VERSION 5.7 ;
  NOWIREEXTENSIONATPIN ON ;
  DIVIDERCHAR "/" ;
  BUSBITCHARS "[]" ;
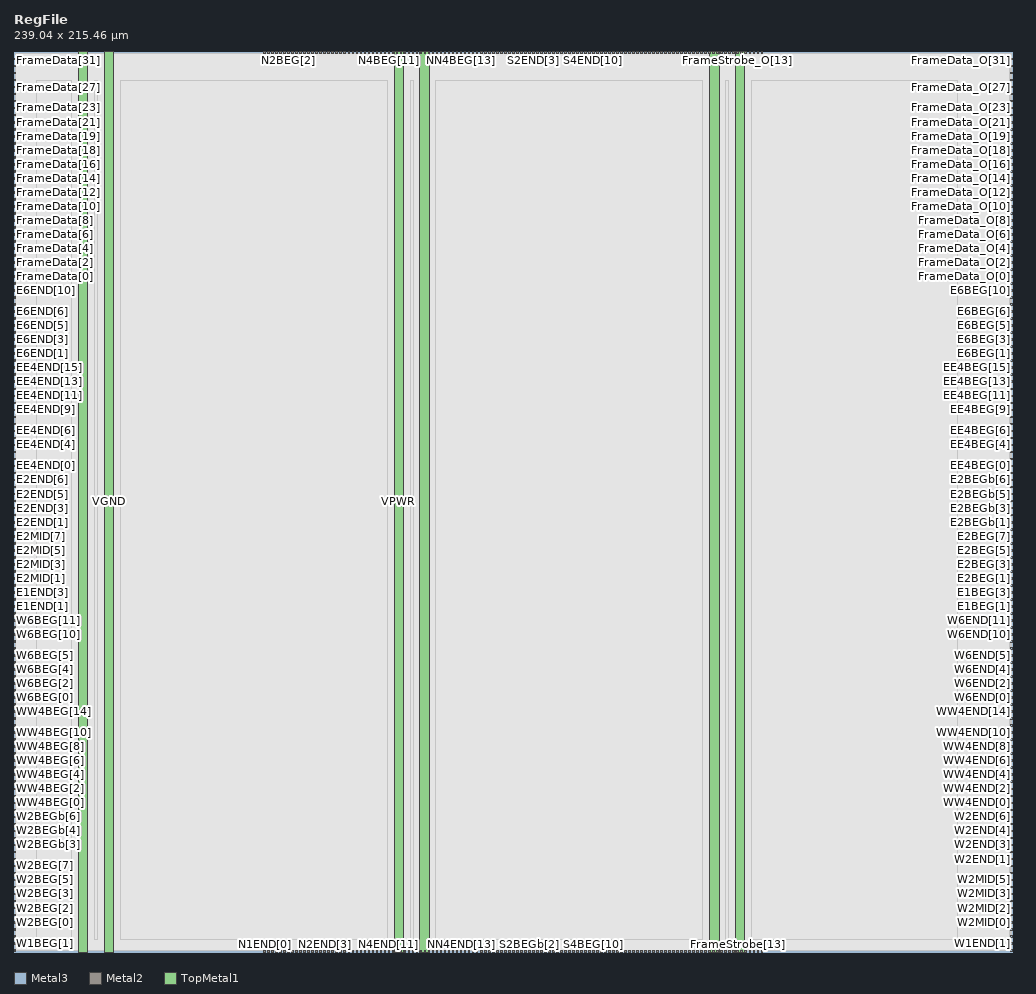
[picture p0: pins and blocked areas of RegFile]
MACRO RegFile
  CLASS BLOCK ;
  FOREIGN RegFile ;
  ORIGIN 0.000 0.000 ;
  SIZE 239.040 BY 215.460 ;
  PIN E1BEG[0]
    DIRECTION OUTPUT ;
    USE SIGNAL ;
    ANTENNADIFFAREA 0.708600 ;
    PORT
      LAYER Metal3 ;
        RECT 238.640 80.860 239.040 81.260 ;
    END
  END E1BEG[0]
  PIN E1BEG[1]
    DIRECTION OUTPUT ;
    USE SIGNAL ;
    ANTENNADIFFAREA 0.708600 ;
    PORT
      LAYER Metal3 ;
        RECT 238.640 82.540 239.040 82.940 ;
    END
  END E1BEG[1]
  PIN E1BEG[2]
    DIRECTION OUTPUT ;
    USE SIGNAL ;
    ANTENNADIFFAREA 0.708600 ;
    PORT
      LAYER Metal3 ;
        RECT 238.640 84.220 239.040 84.620 ;
    END
  END E1BEG[2]
  PIN E1BEG[3]
    DIRECTION OUTPUT ;
    USE SIGNAL ;
    ANTENNADIFFAREA 0.708600 ;
    PORT
      LAYER Metal3 ;
        RECT 238.640 85.900 239.040 86.300 ;
    END
  END E1BEG[3]
  PIN E1END[0]
    DIRECTION INPUT ;
    USE SIGNAL ;
    ANTENNAGATEAREA 1.931800 ;
    PORT
      LAYER Metal3 ;
        RECT 0.000 80.860 0.400 81.260 ;
    END
  END E1END[0]
  PIN E1END[1]
    DIRECTION INPUT ;
    USE SIGNAL ;
    ANTENNAGATEAREA 1.918800 ;
    PORT
      LAYER Metal3 ;
        RECT 0.000 82.540 0.400 82.940 ;
    END
  END E1END[1]
  PIN E1END[2]
    DIRECTION INPUT ;
    USE SIGNAL ;
    ANTENNAGATEAREA 2.371200 ;
    PORT
      LAYER Metal3 ;
        RECT 0.000 84.220 0.400 84.620 ;
    END
  END E1END[2]
  PIN E1END[3]
    DIRECTION INPUT ;
    USE SIGNAL ;
    ANTENNAGATEAREA 2.402400 ;
    PORT
      LAYER Metal3 ;
        RECT 0.000 85.900 0.400 86.300 ;
    END
  END E1END[3]
  PIN E2BEG[0]
    DIRECTION OUTPUT ;
    USE SIGNAL ;
    ANTENNADIFFAREA 0.708600 ;
    PORT
      LAYER Metal3 ;
        RECT 238.640 87.580 239.040 87.980 ;
    END
  END E2BEG[0]
  PIN E2BEG[1]
    DIRECTION OUTPUT ;
    USE SIGNAL ;
    ANTENNADIFFAREA 0.708600 ;
    PORT
      LAYER Metal3 ;
        RECT 238.640 89.260 239.040 89.660 ;
    END
  END E2BEG[1]
  PIN E2BEG[2]
    DIRECTION OUTPUT ;
    USE SIGNAL ;
    ANTENNADIFFAREA 0.708600 ;
    PORT
      LAYER Metal3 ;
        RECT 238.640 90.940 239.040 91.340 ;
    END
  END E2BEG[2]
  PIN E2BEG[3]
    DIRECTION OUTPUT ;
    USE SIGNAL ;
    ANTENNADIFFAREA 0.708600 ;
    PORT
      LAYER Metal3 ;
        RECT 238.640 92.620 239.040 93.020 ;
    END
  END E2BEG[3]
  PIN E2BEG[4]
    DIRECTION OUTPUT ;
    USE SIGNAL ;
    ANTENNADIFFAREA 0.708600 ;
    PORT
      LAYER Metal3 ;
        RECT 238.640 94.300 239.040 94.700 ;
    END
  END E2BEG[4]
  PIN E2BEG[5]
    DIRECTION OUTPUT ;
    USE SIGNAL ;
    ANTENNADIFFAREA 0.708600 ;
    PORT
      LAYER Metal3 ;
        RECT 238.640 95.980 239.040 96.380 ;
    END
  END E2BEG[5]
  PIN E2BEG[6]
    DIRECTION OUTPUT ;
    USE SIGNAL ;
    ANTENNADIFFAREA 0.708600 ;
    PORT
      LAYER Metal3 ;
        RECT 238.640 97.660 239.040 98.060 ;
    END
  END E2BEG[6]
  PIN E2BEG[7]
    DIRECTION OUTPUT ;
    USE SIGNAL ;
    ANTENNADIFFAREA 0.708600 ;
    PORT
      LAYER Metal3 ;
        RECT 238.640 99.340 239.040 99.740 ;
    END
  END E2BEG[7]
  PIN E2BEGb[0]
    DIRECTION OUTPUT ;
    USE SIGNAL ;
    ANTENNADIFFAREA 0.708600 ;
    PORT
      LAYER Metal3 ;
        RECT 238.640 101.020 239.040 101.420 ;
    END
  END E2BEGb[0]
  PIN E2BEGb[1]
    DIRECTION OUTPUT ;
    USE SIGNAL ;
    ANTENNADIFFAREA 0.708600 ;
    PORT
      LAYER Metal3 ;
        RECT 238.640 102.700 239.040 103.100 ;
    END
  END E2BEGb[1]
  PIN E2BEGb[2]
    DIRECTION OUTPUT ;
    USE SIGNAL ;
    ANTENNADIFFAREA 0.708600 ;
    PORT
      LAYER Metal3 ;
        RECT 238.640 104.380 239.040 104.780 ;
    END
  END E2BEGb[2]
  PIN E2BEGb[3]
    DIRECTION OUTPUT ;
    USE SIGNAL ;
    ANTENNADIFFAREA 0.708600 ;
    PORT
      LAYER Metal3 ;
        RECT 238.640 106.060 239.040 106.460 ;
    END
  END E2BEGb[3]
  PIN E2BEGb[4]
    DIRECTION OUTPUT ;
    USE SIGNAL ;
    ANTENNADIFFAREA 0.708600 ;
    PORT
      LAYER Metal3 ;
        RECT 238.640 107.740 239.040 108.140 ;
    END
  END E2BEGb[4]
  PIN E2BEGb[5]
    DIRECTION OUTPUT ;
    USE SIGNAL ;
    ANTENNADIFFAREA 0.708600 ;
    PORT
      LAYER Metal3 ;
        RECT 238.640 109.420 239.040 109.820 ;
    END
  END E2BEGb[5]
  PIN E2BEGb[6]
    DIRECTION OUTPUT ;
    USE SIGNAL ;
    ANTENNADIFFAREA 0.708600 ;
    PORT
      LAYER Metal3 ;
        RECT 238.640 111.100 239.040 111.500 ;
    END
  END E2BEGb[6]
  PIN E2BEGb[7]
    DIRECTION OUTPUT ;
    USE SIGNAL ;
    ANTENNADIFFAREA 0.708600 ;
    PORT
      LAYER Metal3 ;
        RECT 238.640 112.780 239.040 113.180 ;
    END
  END E2BEGb[7]
  PIN E2END[0]
    DIRECTION INPUT ;
    USE SIGNAL ;
    ANTENNAGATEAREA 1.079000 ;
    PORT
      LAYER Metal3 ;
        RECT 0.000 101.020 0.400 101.420 ;
    END
  END E2END[0]
  PIN E2END[1]
    DIRECTION INPUT ;
    USE SIGNAL ;
    ANTENNAGATEAREA 1.033500 ;
    PORT
      LAYER Metal3 ;
        RECT 0.000 102.700 0.400 103.100 ;
    END
  END E2END[1]
  PIN E2END[2]
    DIRECTION INPUT ;
    USE SIGNAL ;
    ANTENNAGATEAREA 1.701700 ;
    PORT
      LAYER Metal3 ;
        RECT 0.000 104.380 0.400 104.780 ;
    END
  END E2END[2]
  PIN E2END[3]
    DIRECTION INPUT ;
    USE SIGNAL ;
    ANTENNAGATEAREA 1.701700 ;
    PORT
      LAYER Metal3 ;
        RECT 0.000 106.060 0.400 106.460 ;
    END
  END E2END[3]
  PIN E2END[4]
    DIRECTION INPUT ;
    USE SIGNAL ;
    ANTENNAGATEAREA 1.079000 ;
    PORT
      LAYER Metal3 ;
        RECT 0.000 107.740 0.400 108.140 ;
    END
  END E2END[4]
  PIN E2END[5]
    DIRECTION INPUT ;
    USE SIGNAL ;
    ANTENNAGATEAREA 1.279200 ;
    PORT
      LAYER Metal3 ;
        RECT 0.000 109.420 0.400 109.820 ;
    END
  END E2END[5]
  PIN E2END[6]
    DIRECTION INPUT ;
    USE SIGNAL ;
    ANTENNAGATEAREA 1.292200 ;
    PORT
      LAYER Metal3 ;
        RECT 0.000 111.100 0.400 111.500 ;
    END
  END E2END[6]
  PIN E2END[7]
    DIRECTION INPUT ;
    USE SIGNAL ;
    ANTENNAGATEAREA 1.033500 ;
    PORT
      LAYER Metal3 ;
        RECT 0.000 112.780 0.400 113.180 ;
    END
  END E2END[7]
  PIN E2MID[0]
    DIRECTION INPUT ;
    USE SIGNAL ;
    ANTENNAGATEAREA 0.816400 ;
    PORT
      LAYER Metal3 ;
        RECT 0.000 87.580 0.400 87.980 ;
    END
  END E2MID[0]
  PIN E2MID[1]
    DIRECTION INPUT ;
    USE SIGNAL ;
    ANTENNAGATEAREA 1.014000 ;
    PORT
      LAYER Metal3 ;
        RECT 0.000 89.260 0.400 89.660 ;
    END
  END E2MID[1]
  PIN E2MID[2]
    DIRECTION INPUT ;
    USE SIGNAL ;
    ANTENNAGATEAREA 0.820300 ;
    PORT
      LAYER Metal3 ;
        RECT 0.000 90.940 0.400 91.340 ;
    END
  END E2MID[2]
  PIN E2MID[3]
    DIRECTION INPUT ;
    USE SIGNAL ;
    ANTENNAGATEAREA 1.033500 ;
    PORT
      LAYER Metal3 ;
        RECT 0.000 92.620 0.400 93.020 ;
    END
  END E2MID[3]
  PIN E2MID[4]
    DIRECTION INPUT ;
    USE SIGNAL ;
    ANTENNAGATEAREA 0.820300 ;
    PORT
      LAYER Metal3 ;
        RECT 0.000 94.300 0.400 94.700 ;
    END
  END E2MID[4]
  PIN E2MID[5]
    DIRECTION INPUT ;
    USE SIGNAL ;
    ANTENNAGATEAREA 1.033500 ;
    PORT
      LAYER Metal3 ;
        RECT 0.000 95.980 0.400 96.380 ;
    END
  END E2MID[5]
  PIN E2MID[6]
    DIRECTION INPUT ;
    USE SIGNAL ;
    ANTENNAGATEAREA 0.787800 ;
    PORT
      LAYER Metal3 ;
        RECT 0.000 97.660 0.400 98.060 ;
    END
  END E2MID[6]
  PIN E2MID[7]
    DIRECTION INPUT ;
    USE SIGNAL ;
    ANTENNAGATEAREA 1.001000 ;
    PORT
      LAYER Metal3 ;
        RECT 0.000 99.340 0.400 99.740 ;
    END
  END E2MID[7]
  PIN E6BEG[0]
    DIRECTION OUTPUT ;
    USE SIGNAL ;
    ANTENNADIFFAREA 0.708600 ;
    PORT
      LAYER Metal3 ;
        RECT 238.640 141.340 239.040 141.740 ;
    END
  END E6BEG[0]
  PIN E6BEG[10]
    DIRECTION OUTPUT ;
    USE SIGNAL ;
    ANTENNADIFFAREA 0.708600 ;
    PORT
      LAYER Metal3 ;
        RECT 238.640 158.140 239.040 158.540 ;
    END
  END E6BEG[10]
  PIN E6BEG[11]
    DIRECTION OUTPUT ;
    USE SIGNAL ;
    ANTENNADIFFAREA 0.708600 ;
    PORT
      LAYER Metal3 ;
        RECT 238.640 159.820 239.040 160.220 ;
    END
  END E6BEG[11]
  PIN E6BEG[1]
    DIRECTION OUTPUT ;
    USE SIGNAL ;
    ANTENNADIFFAREA 0.708600 ;
    PORT
      LAYER Metal3 ;
        RECT 238.640 143.020 239.040 143.420 ;
    END
  END E6BEG[1]
  PIN E6BEG[2]
    DIRECTION OUTPUT ;
    USE SIGNAL ;
    ANTENNADIFFAREA 0.708600 ;
    PORT
      LAYER Metal3 ;
        RECT 238.640 144.700 239.040 145.100 ;
    END
  END E6BEG[2]
  PIN E6BEG[3]
    DIRECTION OUTPUT ;
    USE SIGNAL ;
    ANTENNADIFFAREA 0.708600 ;
    PORT
      LAYER Metal3 ;
        RECT 238.640 146.380 239.040 146.780 ;
    END
  END E6BEG[3]
  PIN E6BEG[4]
    DIRECTION OUTPUT ;
    USE SIGNAL ;
    ANTENNADIFFAREA 0.708600 ;
    PORT
      LAYER Metal3 ;
        RECT 238.640 148.060 239.040 148.460 ;
    END
  END E6BEG[4]
  PIN E6BEG[5]
    DIRECTION OUTPUT ;
    USE SIGNAL ;
    ANTENNADIFFAREA 0.708600 ;
    PORT
      LAYER Metal3 ;
        RECT 238.640 149.740 239.040 150.140 ;
    END
  END E6BEG[5]
  PIN E6BEG[6]
    DIRECTION OUTPUT ;
    USE SIGNAL ;
    ANTENNADIFFAREA 0.708600 ;
    PORT
      LAYER Metal3 ;
        RECT 238.640 151.420 239.040 151.820 ;
    END
  END E6BEG[6]
  PIN E6BEG[7]
    DIRECTION OUTPUT ;
    USE SIGNAL ;
    ANTENNADIFFAREA 0.708600 ;
    PORT
      LAYER Metal3 ;
        RECT 238.640 153.100 239.040 153.500 ;
    END
  END E6BEG[7]
  PIN E6BEG[8]
    DIRECTION OUTPUT ;
    USE SIGNAL ;
    ANTENNADIFFAREA 0.708600 ;
    PORT
      LAYER Metal3 ;
        RECT 238.640 154.780 239.040 155.180 ;
    END
  END E6BEG[8]
  PIN E6BEG[9]
    DIRECTION OUTPUT ;
    USE SIGNAL ;
    ANTENNADIFFAREA 0.708600 ;
    PORT
      LAYER Metal3 ;
        RECT 238.640 156.460 239.040 156.860 ;
    END
  END E6BEG[9]
  PIN E6END[0]
    DIRECTION INPUT ;
    USE SIGNAL ;
    ANTENNAGATEAREA 2.596100 ;
    PORT
      LAYER Metal3 ;
        RECT 0.000 141.340 0.400 141.740 ;
    END
  END E6END[0]
  PIN E6END[10]
    DIRECTION INPUT ;
    USE SIGNAL ;
    ANTENNAGATEAREA 0.180700 ;
    PORT
      LAYER Metal3 ;
        RECT 0.000 158.140 0.400 158.540 ;
    END
  END E6END[10]
  PIN E6END[11]
    DIRECTION INPUT ;
    USE SIGNAL ;
    ANTENNAGATEAREA 0.180700 ;
    PORT
      LAYER Metal3 ;
        RECT 0.000 159.820 0.400 160.220 ;
    END
  END E6END[11]
  PIN E6END[1]
    DIRECTION INPUT ;
    USE SIGNAL ;
    ANTENNAGATEAREA 2.567500 ;
    PORT
      LAYER Metal3 ;
        RECT 0.000 143.020 0.400 143.420 ;
    END
  END E6END[1]
  PIN E6END[2]
    DIRECTION INPUT ;
    USE SIGNAL ;
    ANTENNAGATEAREA 0.180700 ;
    PORT
      LAYER Metal3 ;
        RECT 0.000 144.700 0.400 145.100 ;
    END
  END E6END[2]
  PIN E6END[3]
    DIRECTION INPUT ;
    USE SIGNAL ;
    ANTENNAGATEAREA 0.180700 ;
    PORT
      LAYER Metal3 ;
        RECT 0.000 146.380 0.400 146.780 ;
    END
  END E6END[3]
  PIN E6END[4]
    DIRECTION INPUT ;
    USE SIGNAL ;
    ANTENNAGATEAREA 0.180700 ;
    PORT
      LAYER Metal3 ;
        RECT 0.000 148.060 0.400 148.460 ;
    END
  END E6END[4]
  PIN E6END[5]
    DIRECTION INPUT ;
    USE SIGNAL ;
    ANTENNAGATEAREA 0.180700 ;
    PORT
      LAYER Metal3 ;
        RECT 0.000 149.740 0.400 150.140 ;
    END
  END E6END[5]
  PIN E6END[6]
    DIRECTION INPUT ;
    USE SIGNAL ;
    ANTENNAGATEAREA 0.180700 ;
    PORT
      LAYER Metal3 ;
        RECT 0.000 151.420 0.400 151.820 ;
    END
  END E6END[6]
  PIN E6END[7]
    DIRECTION INPUT ;
    USE SIGNAL ;
    ANTENNAGATEAREA 0.180700 ;
    PORT
      LAYER Metal3 ;
        RECT 0.000 153.100 0.400 153.500 ;
    END
  END E6END[7]
  PIN E6END[8]
    DIRECTION INPUT ;
    USE SIGNAL ;
    ANTENNAGATEAREA 0.180700 ;
    PORT
      LAYER Metal3 ;
        RECT 0.000 154.780 0.400 155.180 ;
    END
  END E6END[8]
  PIN E6END[9]
    DIRECTION INPUT ;
    USE SIGNAL ;
    ANTENNAGATEAREA 0.180700 ;
    PORT
      LAYER Metal3 ;
        RECT 0.000 156.460 0.400 156.860 ;
    END
  END E6END[9]
  PIN EE4BEG[0]
    DIRECTION OUTPUT ;
    USE SIGNAL ;
    ANTENNADIFFAREA 0.708600 ;
    PORT
      LAYER Metal3 ;
        RECT 238.640 114.460 239.040 114.860 ;
    END
  END EE4BEG[0]
  PIN EE4BEG[10]
    DIRECTION OUTPUT ;
    USE SIGNAL ;
    ANTENNADIFFAREA 0.708600 ;
    PORT
      LAYER Metal3 ;
        RECT 238.640 131.260 239.040 131.660 ;
    END
  END EE4BEG[10]
  PIN EE4BEG[11]
    DIRECTION OUTPUT ;
    USE SIGNAL ;
    ANTENNADIFFAREA 0.708600 ;
    PORT
      LAYER Metal3 ;
        RECT 238.640 132.940 239.040 133.340 ;
    END
  END EE4BEG[11]
  PIN EE4BEG[12]
    DIRECTION OUTPUT ;
    USE SIGNAL ;
    ANTENNADIFFAREA 0.708600 ;
    PORT
      LAYER Metal3 ;
        RECT 238.640 134.620 239.040 135.020 ;
    END
  END EE4BEG[12]
  PIN EE4BEG[13]
    DIRECTION OUTPUT ;
    USE SIGNAL ;
    ANTENNADIFFAREA 0.708600 ;
    PORT
      LAYER Metal3 ;
        RECT 238.640 136.300 239.040 136.700 ;
    END
  END EE4BEG[13]
  PIN EE4BEG[14]
    DIRECTION OUTPUT ;
    USE SIGNAL ;
    ANTENNADIFFAREA 0.708600 ;
    PORT
      LAYER Metal3 ;
        RECT 238.640 137.980 239.040 138.380 ;
    END
  END EE4BEG[14]
  PIN EE4BEG[15]
    DIRECTION OUTPUT ;
    USE SIGNAL ;
    ANTENNADIFFAREA 0.708600 ;
    PORT
      LAYER Metal3 ;
        RECT 238.640 139.660 239.040 140.060 ;
    END
  END EE4BEG[15]
  PIN EE4BEG[1]
    DIRECTION OUTPUT ;
    USE SIGNAL ;
    ANTENNADIFFAREA 0.708600 ;
    PORT
      LAYER Metal3 ;
        RECT 238.640 116.140 239.040 116.540 ;
    END
  END EE4BEG[1]
  PIN EE4BEG[2]
    DIRECTION OUTPUT ;
    USE SIGNAL ;
    ANTENNADIFFAREA 0.708600 ;
    PORT
      LAYER Metal3 ;
        RECT 238.640 117.820 239.040 118.220 ;
    END
  END EE4BEG[2]
  PIN EE4BEG[3]
    DIRECTION OUTPUT ;
    USE SIGNAL ;
    ANTENNADIFFAREA 0.708600 ;
    PORT
      LAYER Metal3 ;
        RECT 238.640 119.500 239.040 119.900 ;
    END
  END EE4BEG[3]
  PIN EE4BEG[4]
    DIRECTION OUTPUT ;
    USE SIGNAL ;
    ANTENNADIFFAREA 0.708600 ;
    PORT
      LAYER Metal3 ;
        RECT 238.640 121.180 239.040 121.580 ;
    END
  END EE4BEG[4]
  PIN EE4BEG[5]
    DIRECTION OUTPUT ;
    USE SIGNAL ;
    ANTENNADIFFAREA 0.708600 ;
    PORT
      LAYER Metal3 ;
        RECT 238.640 122.860 239.040 123.260 ;
    END
  END EE4BEG[5]
  PIN EE4BEG[6]
    DIRECTION OUTPUT ;
    USE SIGNAL ;
    ANTENNADIFFAREA 0.708600 ;
    PORT
      LAYER Metal3 ;
        RECT 238.640 124.540 239.040 124.940 ;
    END
  END EE4BEG[6]
  PIN EE4BEG[7]
    DIRECTION OUTPUT ;
    USE SIGNAL ;
    ANTENNADIFFAREA 0.708600 ;
    PORT
      LAYER Metal3 ;
        RECT 238.640 126.220 239.040 126.620 ;
    END
  END EE4BEG[7]
  PIN EE4BEG[8]
    DIRECTION OUTPUT ;
    USE SIGNAL ;
    ANTENNADIFFAREA 0.708600 ;
    PORT
      LAYER Metal3 ;
        RECT 238.640 127.900 239.040 128.300 ;
    END
  END EE4BEG[8]
  PIN EE4BEG[9]
    DIRECTION OUTPUT ;
    USE SIGNAL ;
    ANTENNADIFFAREA 0.708600 ;
    PORT
      LAYER Metal3 ;
        RECT 238.640 129.580 239.040 129.980 ;
    END
  END EE4BEG[9]
  PIN EE4END[0]
    DIRECTION INPUT ;
    USE SIGNAL ;
    ANTENNAGATEAREA 0.881400 ;
    PORT
      LAYER Metal3 ;
        RECT 0.000 114.460 0.400 114.860 ;
    END
  END EE4END[0]
  PIN EE4END[10]
    DIRECTION INPUT ;
    USE SIGNAL ;
    ANTENNAGATEAREA 0.789100 ;
    ANTENNADIFFAREA 2.015400 ;
    PORT
      LAYER Metal3 ;
        RECT 0.000 131.260 0.400 131.660 ;
    END
  END EE4END[10]
  PIN EE4END[11]
    DIRECTION INPUT ;
    USE SIGNAL ;
    ANTENNAGATEAREA 0.789100 ;
    ANTENNADIFFAREA 2.015400 ;
    PORT
      LAYER Metal3 ;
        RECT 0.000 132.940 0.400 133.340 ;
    END
  END EE4END[11]
  PIN EE4END[12]
    DIRECTION INPUT ;
    USE SIGNAL ;
    ANTENNAGATEAREA 0.789100 ;
    ANTENNADIFFAREA 2.015400 ;
    PORT
      LAYER Metal3 ;
        RECT 0.000 134.620 0.400 135.020 ;
    END
  END EE4END[12]
  PIN EE4END[13]
    DIRECTION INPUT ;
    USE SIGNAL ;
    ANTENNAGATEAREA 0.180700 ;
    PORT
      LAYER Metal3 ;
        RECT 0.000 136.300 0.400 136.700 ;
    END
  END EE4END[13]
  PIN EE4END[14]
    DIRECTION INPUT ;
    USE SIGNAL ;
    ANTENNAGATEAREA 0.180700 ;
    PORT
      LAYER Metal3 ;
        RECT 0.000 137.980 0.400 138.380 ;
    END
  END EE4END[14]
  PIN EE4END[15]
    DIRECTION INPUT ;
    USE SIGNAL ;
    ANTENNAGATEAREA 0.789100 ;
    ANTENNADIFFAREA 2.015400 ;
    PORT
      LAYER Metal3 ;
        RECT 0.000 139.660 0.400 140.060 ;
    END
  END EE4END[15]
  PIN EE4END[1]
    DIRECTION INPUT ;
    USE SIGNAL ;
    ANTENNAGATEAREA 0.852800 ;
    PORT
      LAYER Metal3 ;
        RECT 0.000 116.140 0.400 116.540 ;
    END
  END EE4END[1]
  PIN EE4END[2]
    DIRECTION INPUT ;
    USE SIGNAL ;
    ANTENNAGATEAREA 0.852800 ;
    PORT
      LAYER Metal3 ;
        RECT 0.000 117.820 0.400 118.220 ;
    END
  END EE4END[2]
  PIN EE4END[3]
    DIRECTION INPUT ;
    USE SIGNAL ;
    ANTENNAGATEAREA 0.878800 ;
    PORT
      LAYER Metal3 ;
        RECT 0.000 119.500 0.400 119.900 ;
    END
  END EE4END[3]
  PIN EE4END[4]
    DIRECTION INPUT ;
    USE SIGNAL ;
    ANTENNAGATEAREA 0.789100 ;
    ANTENNADIFFAREA 2.015400 ;
    PORT
      LAYER Metal3 ;
        RECT 0.000 121.180 0.400 121.580 ;
    END
  END EE4END[4]
  PIN EE4END[5]
    DIRECTION INPUT ;
    USE SIGNAL ;
    ANTENNAGATEAREA 0.789100 ;
    ANTENNADIFFAREA 2.015400 ;
    PORT
      LAYER Metal3 ;
        RECT 0.000 122.860 0.400 123.260 ;
    END
  END EE4END[5]
  PIN EE4END[6]
    DIRECTION INPUT ;
    USE SIGNAL ;
    ANTENNAGATEAREA 0.789100 ;
    ANTENNADIFFAREA 2.015400 ;
    PORT
      LAYER Metal3 ;
        RECT 0.000 124.540 0.400 124.940 ;
    END
  END EE4END[6]
  PIN EE4END[7]
    DIRECTION INPUT ;
    USE SIGNAL ;
    ANTENNAGATEAREA 0.789100 ;
    ANTENNADIFFAREA 2.015400 ;
    PORT
      LAYER Metal3 ;
        RECT 0.000 126.220 0.400 126.620 ;
    END
  END EE4END[7]
  PIN EE4END[8]
    DIRECTION INPUT ;
    USE SIGNAL ;
    ANTENNAGATEAREA 0.789100 ;
    ANTENNADIFFAREA 2.015400 ;
    PORT
      LAYER Metal3 ;
        RECT 0.000 127.900 0.400 128.300 ;
    END
  END EE4END[8]
  PIN EE4END[9]
    DIRECTION INPUT ;
    USE SIGNAL ;
    ANTENNAGATEAREA 0.789100 ;
    ANTENNADIFFAREA 2.015400 ;
    PORT
      LAYER Metal3 ;
        RECT 0.000 129.580 0.400 129.980 ;
    END
  END EE4END[9]
  PIN FrameData[0]
    DIRECTION INPUT ;
    USE SIGNAL ;
    ANTENNAGATEAREA 2.349100 ;
    PORT
      LAYER Metal3 ;
        RECT 0.000 161.500 0.400 161.900 ;
    END
  END FrameData[0]
  PIN FrameData[10]
    DIRECTION INPUT ;
    USE SIGNAL ;
    ANTENNAGATEAREA 2.529800 ;
    PORT
      LAYER Metal3 ;
        RECT 0.000 178.300 0.400 178.700 ;
    END
  END FrameData[10]
  PIN FrameData[11]
    DIRECTION INPUT ;
    USE SIGNAL ;
    ANTENNAGATEAREA 2.529800 ;
    PORT
      LAYER Metal3 ;
        RECT 0.000 179.980 0.400 180.380 ;
    END
  END FrameData[11]
  PIN FrameData[12]
    DIRECTION INPUT ;
    USE SIGNAL ;
    ANTENNAGATEAREA 2.529800 ;
    PORT
      LAYER Metal3 ;
        RECT 0.000 181.660 0.400 182.060 ;
    END
  END FrameData[12]
  PIN FrameData[13]
    DIRECTION INPUT ;
    USE SIGNAL ;
    ANTENNAGATEAREA 2.529800 ;
    PORT
      LAYER Metal3 ;
        RECT 0.000 183.340 0.400 183.740 ;
    END
  END FrameData[13]
  PIN FrameData[14]
    DIRECTION INPUT ;
    USE SIGNAL ;
    ANTENNAGATEAREA 2.529800 ;
    PORT
      LAYER Metal3 ;
        RECT 0.000 185.020 0.400 185.420 ;
    END
  END FrameData[14]
  PIN FrameData[15]
    DIRECTION INPUT ;
    USE SIGNAL ;
    ANTENNAGATEAREA 2.529800 ;
    PORT
      LAYER Metal3 ;
        RECT 0.000 186.700 0.400 187.100 ;
    END
  END FrameData[15]
  PIN FrameData[16]
    DIRECTION INPUT ;
    USE SIGNAL ;
    ANTENNAGATEAREA 2.529800 ;
    PORT
      LAYER Metal3 ;
        RECT 0.000 188.380 0.400 188.780 ;
    END
  END FrameData[16]
  PIN FrameData[17]
    DIRECTION INPUT ;
    USE SIGNAL ;
    ANTENNAGATEAREA 2.529800 ;
    PORT
      LAYER Metal3 ;
        RECT 0.000 190.060 0.400 190.460 ;
    END
  END FrameData[17]
  PIN FrameData[18]
    DIRECTION INPUT ;
    USE SIGNAL ;
    ANTENNAGATEAREA 2.529800 ;
    PORT
      LAYER Metal3 ;
        RECT 0.000 191.740 0.400 192.140 ;
    END
  END FrameData[18]
  PIN FrameData[19]
    DIRECTION INPUT ;
    USE SIGNAL ;
    ANTENNAGATEAREA 2.529800 ;
    PORT
      LAYER Metal3 ;
        RECT 0.000 193.420 0.400 193.820 ;
    END
  END FrameData[19]
  PIN FrameData[1]
    DIRECTION INPUT ;
    USE SIGNAL ;
    ANTENNAGATEAREA 2.349100 ;
    PORT
      LAYER Metal3 ;
        RECT 0.000 163.180 0.400 163.580 ;
    END
  END FrameData[1]
  PIN FrameData[20]
    DIRECTION INPUT ;
    USE SIGNAL ;
    ANTENNAGATEAREA 2.529800 ;
    PORT
      LAYER Metal3 ;
        RECT 0.000 195.100 0.400 195.500 ;
    END
  END FrameData[20]
  PIN FrameData[21]
    DIRECTION INPUT ;
    USE SIGNAL ;
    ANTENNAGATEAREA 2.529800 ;
    PORT
      LAYER Metal3 ;
        RECT 0.000 196.780 0.400 197.180 ;
    END
  END FrameData[21]
  PIN FrameData[22]
    DIRECTION INPUT ;
    USE SIGNAL ;
    ANTENNAGATEAREA 2.529800 ;
    PORT
      LAYER Metal3 ;
        RECT 0.000 198.460 0.400 198.860 ;
    END
  END FrameData[22]
  PIN FrameData[23]
    DIRECTION INPUT ;
    USE SIGNAL ;
    ANTENNAGATEAREA 2.529800 ;
    PORT
      LAYER Metal3 ;
        RECT 0.000 200.140 0.400 200.540 ;
    END
  END FrameData[23]
  PIN FrameData[24]
    DIRECTION INPUT ;
    USE SIGNAL ;
    ANTENNAGATEAREA 2.529800 ;
    PORT
      LAYER Metal3 ;
        RECT 0.000 201.820 0.400 202.220 ;
    END
  END FrameData[24]
  PIN FrameData[25]
    DIRECTION INPUT ;
    USE SIGNAL ;
    ANTENNAGATEAREA 2.529800 ;
    PORT
      LAYER Metal3 ;
        RECT 0.000 203.500 0.400 203.900 ;
    END
  END FrameData[25]
  PIN FrameData[26]
    DIRECTION INPUT ;
    USE SIGNAL ;
    ANTENNAGATEAREA 2.529800 ;
    PORT
      LAYER Metal3 ;
        RECT 0.000 205.180 0.400 205.580 ;
    END
  END FrameData[26]
  PIN FrameData[27]
    DIRECTION INPUT ;
    USE SIGNAL ;
    ANTENNAGATEAREA 2.529800 ;
    PORT
      LAYER Metal3 ;
        RECT 0.000 206.860 0.400 207.260 ;
    END
  END FrameData[27]
  PIN FrameData[28]
    DIRECTION INPUT ;
    USE SIGNAL ;
    ANTENNAGATEAREA 2.529800 ;
    PORT
      LAYER Metal3 ;
        RECT 0.000 208.540 0.400 208.940 ;
    END
  END FrameData[28]
  PIN FrameData[29]
    DIRECTION INPUT ;
    USE SIGNAL ;
    ANTENNAGATEAREA 2.529800 ;
    PORT
      LAYER Metal3 ;
        RECT 0.000 210.220 0.400 210.620 ;
    END
  END FrameData[29]
  PIN FrameData[2]
    DIRECTION INPUT ;
    USE SIGNAL ;
    ANTENNAGATEAREA 2.529800 ;
    PORT
      LAYER Metal3 ;
        RECT 0.000 164.860 0.400 165.260 ;
    END
  END FrameData[2]
  PIN FrameData[30]
    DIRECTION INPUT ;
    USE SIGNAL ;
    ANTENNAGATEAREA 2.529800 ;
    PORT
      LAYER Metal3 ;
        RECT 0.000 211.900 0.400 212.300 ;
    END
  END FrameData[30]
  PIN FrameData[31]
    DIRECTION INPUT ;
    USE SIGNAL ;
    ANTENNAGATEAREA 2.529800 ;
    PORT
      LAYER Metal3 ;
        RECT 0.000 213.580 0.400 213.980 ;
    END
  END FrameData[31]
  PIN FrameData[3]
    DIRECTION INPUT ;
    USE SIGNAL ;
    ANTENNAGATEAREA 2.529800 ;
    PORT
      LAYER Metal3 ;
        RECT 0.000 166.540 0.400 166.940 ;
    END
  END FrameData[3]
  PIN FrameData[4]
    DIRECTION INPUT ;
    USE SIGNAL ;
    ANTENNAGATEAREA 2.529800 ;
    PORT
      LAYER Metal3 ;
        RECT 0.000 168.220 0.400 168.620 ;
    END
  END FrameData[4]
  PIN FrameData[5]
    DIRECTION INPUT ;
    USE SIGNAL ;
    ANTENNAGATEAREA 2.529800 ;
    PORT
      LAYER Metal3 ;
        RECT 0.000 169.900 0.400 170.300 ;
    END
  END FrameData[5]
  PIN FrameData[6]
    DIRECTION INPUT ;
    USE SIGNAL ;
    ANTENNAGATEAREA 2.529800 ;
    PORT
      LAYER Metal3 ;
        RECT 0.000 171.580 0.400 171.980 ;
    END
  END FrameData[6]
  PIN FrameData[7]
    DIRECTION INPUT ;
    USE SIGNAL ;
    ANTENNAGATEAREA 2.529800 ;
    PORT
      LAYER Metal3 ;
        RECT 0.000 173.260 0.400 173.660 ;
    END
  END FrameData[7]
  PIN FrameData[8]
    DIRECTION INPUT ;
    USE SIGNAL ;
    ANTENNAGATEAREA 2.529800 ;
    PORT
      LAYER Metal3 ;
        RECT 0.000 174.940 0.400 175.340 ;
    END
  END FrameData[8]
  PIN FrameData[9]
    DIRECTION INPUT ;
    USE SIGNAL ;
    ANTENNAGATEAREA 2.529800 ;
    PORT
      LAYER Metal3 ;
        RECT 0.000 176.620 0.400 177.020 ;
    END
  END FrameData[9]
  PIN FrameData_O[0]
    DIRECTION OUTPUT ;
    USE SIGNAL ;
    ANTENNADIFFAREA 0.708600 ;
    PORT
      LAYER Metal3 ;
        RECT 238.640 161.500 239.040 161.900 ;
    END
  END FrameData_O[0]
  PIN FrameData_O[10]
    DIRECTION OUTPUT ;
    USE SIGNAL ;
    ANTENNADIFFAREA 0.708600 ;
    PORT
      LAYER Metal3 ;
        RECT 238.640 178.300 239.040 178.700 ;
    END
  END FrameData_O[10]
  PIN FrameData_O[11]
    DIRECTION OUTPUT ;
    USE SIGNAL ;
    ANTENNADIFFAREA 0.708600 ;
    PORT
      LAYER Metal3 ;
        RECT 238.640 179.980 239.040 180.380 ;
    END
  END FrameData_O[11]
  PIN FrameData_O[12]
    DIRECTION OUTPUT ;
    USE SIGNAL ;
    ANTENNADIFFAREA 0.708600 ;
    PORT
      LAYER Metal3 ;
        RECT 238.640 181.660 239.040 182.060 ;
    END
  END FrameData_O[12]
  PIN FrameData_O[13]
    DIRECTION OUTPUT ;
    USE SIGNAL ;
    ANTENNADIFFAREA 0.708600 ;
    PORT
      LAYER Metal3 ;
        RECT 238.640 183.340 239.040 183.740 ;
    END
  END FrameData_O[13]
  PIN FrameData_O[14]
    DIRECTION OUTPUT ;
    USE SIGNAL ;
    ANTENNADIFFAREA 0.708600 ;
    PORT
      LAYER Metal3 ;
        RECT 238.640 185.020 239.040 185.420 ;
    END
  END FrameData_O[14]
  PIN FrameData_O[15]
    DIRECTION OUTPUT ;
    USE SIGNAL ;
    ANTENNADIFFAREA 0.708600 ;
    PORT
      LAYER Metal3 ;
        RECT 238.640 186.700 239.040 187.100 ;
    END
  END FrameData_O[15]
  PIN FrameData_O[16]
    DIRECTION OUTPUT ;
    USE SIGNAL ;
    ANTENNADIFFAREA 0.708600 ;
    PORT
      LAYER Metal3 ;
        RECT 238.640 188.380 239.040 188.780 ;
    END
  END FrameData_O[16]
  PIN FrameData_O[17]
    DIRECTION OUTPUT ;
    USE SIGNAL ;
    ANTENNADIFFAREA 0.708600 ;
    PORT
      LAYER Metal3 ;
        RECT 238.640 190.060 239.040 190.460 ;
    END
  END FrameData_O[17]
  PIN FrameData_O[18]
    DIRECTION OUTPUT ;
    USE SIGNAL ;
    ANTENNADIFFAREA 0.708600 ;
    PORT
      LAYER Metal3 ;
        RECT 238.640 191.740 239.040 192.140 ;
    END
  END FrameData_O[18]
  PIN FrameData_O[19]
    DIRECTION OUTPUT ;
    USE SIGNAL ;
    ANTENNADIFFAREA 0.708600 ;
    PORT
      LAYER Metal3 ;
        RECT 238.640 193.420 239.040 193.820 ;
    END
  END FrameData_O[19]
  PIN FrameData_O[1]
    DIRECTION OUTPUT ;
    USE SIGNAL ;
    ANTENNADIFFAREA 0.708600 ;
    PORT
      LAYER Metal3 ;
        RECT 238.640 163.180 239.040 163.580 ;
    END
  END FrameData_O[1]
  PIN FrameData_O[20]
    DIRECTION OUTPUT ;
    USE SIGNAL ;
    ANTENNADIFFAREA 0.708600 ;
    PORT
      LAYER Metal3 ;
        RECT 238.640 195.100 239.040 195.500 ;
    END
  END FrameData_O[20]
  PIN FrameData_O[21]
    DIRECTION OUTPUT ;
    USE SIGNAL ;
    ANTENNADIFFAREA 0.708600 ;
    PORT
      LAYER Metal3 ;
        RECT 238.640 196.780 239.040 197.180 ;
    END
  END FrameData_O[21]
  PIN FrameData_O[22]
    DIRECTION OUTPUT ;
    USE SIGNAL ;
    ANTENNADIFFAREA 0.708600 ;
    PORT
      LAYER Metal3 ;
        RECT 238.640 198.460 239.040 198.860 ;
    END
  END FrameData_O[22]
  PIN FrameData_O[23]
    DIRECTION OUTPUT ;
    USE SIGNAL ;
    ANTENNADIFFAREA 0.708600 ;
    PORT
      LAYER Metal3 ;
        RECT 238.640 200.140 239.040 200.540 ;
    END
  END FrameData_O[23]
  PIN FrameData_O[24]
    DIRECTION OUTPUT ;
    USE SIGNAL ;
    ANTENNADIFFAREA 0.708600 ;
    PORT
      LAYER Metal3 ;
        RECT 238.640 201.820 239.040 202.220 ;
    END
  END FrameData_O[24]
  PIN FrameData_O[25]
    DIRECTION OUTPUT ;
    USE SIGNAL ;
    ANTENNADIFFAREA 0.708600 ;
    PORT
      LAYER Metal3 ;
        RECT 238.640 203.500 239.040 203.900 ;
    END
  END FrameData_O[25]
  PIN FrameData_O[26]
    DIRECTION OUTPUT ;
    USE SIGNAL ;
    ANTENNADIFFAREA 0.708600 ;
    PORT
      LAYER Metal3 ;
        RECT 238.640 205.180 239.040 205.580 ;
    END
  END FrameData_O[26]
  PIN FrameData_O[27]
    DIRECTION OUTPUT ;
    USE SIGNAL ;
    ANTENNADIFFAREA 0.708600 ;
    PORT
      LAYER Metal3 ;
        RECT 238.640 206.860 239.040 207.260 ;
    END
  END FrameData_O[27]
  PIN FrameData_O[28]
    DIRECTION OUTPUT ;
    USE SIGNAL ;
    ANTENNADIFFAREA 0.708600 ;
    PORT
      LAYER Metal3 ;
        RECT 238.640 208.540 239.040 208.940 ;
    END
  END FrameData_O[28]
  PIN FrameData_O[29]
    DIRECTION OUTPUT ;
    USE SIGNAL ;
    ANTENNADIFFAREA 0.708600 ;
    PORT
      LAYER Metal3 ;
        RECT 238.640 210.220 239.040 210.620 ;
    END
  END FrameData_O[29]
  PIN FrameData_O[2]
    DIRECTION OUTPUT ;
    USE SIGNAL ;
    ANTENNADIFFAREA 0.708600 ;
    PORT
      LAYER Metal3 ;
        RECT 238.640 164.860 239.040 165.260 ;
    END
  END FrameData_O[2]
  PIN FrameData_O[30]
    DIRECTION OUTPUT ;
    USE SIGNAL ;
    ANTENNADIFFAREA 0.708600 ;
    PORT
      LAYER Metal3 ;
        RECT 238.640 211.900 239.040 212.300 ;
    END
  END FrameData_O[30]
  PIN FrameData_O[31]
    DIRECTION OUTPUT ;
    USE SIGNAL ;
    ANTENNADIFFAREA 0.708600 ;
    PORT
      LAYER Metal3 ;
        RECT 238.640 213.580 239.040 213.980 ;
    END
  END FrameData_O[31]
  PIN FrameData_O[3]
    DIRECTION OUTPUT ;
    USE SIGNAL ;
    ANTENNADIFFAREA 0.708600 ;
    PORT
      LAYER Metal3 ;
        RECT 238.640 166.540 239.040 166.940 ;
    END
  END FrameData_O[3]
  PIN FrameData_O[4]
    DIRECTION OUTPUT ;
    USE SIGNAL ;
    ANTENNADIFFAREA 0.708600 ;
    PORT
      LAYER Metal3 ;
        RECT 238.640 168.220 239.040 168.620 ;
    END
  END FrameData_O[4]
  PIN FrameData_O[5]
    DIRECTION OUTPUT ;
    USE SIGNAL ;
    ANTENNADIFFAREA 0.708600 ;
    PORT
      LAYER Metal3 ;
        RECT 238.640 169.900 239.040 170.300 ;
    END
  END FrameData_O[5]
  PIN FrameData_O[6]
    DIRECTION OUTPUT ;
    USE SIGNAL ;
    ANTENNADIFFAREA 0.708600 ;
    PORT
      LAYER Metal3 ;
        RECT 238.640 171.580 239.040 171.980 ;
    END
  END FrameData_O[6]
  PIN FrameData_O[7]
    DIRECTION OUTPUT ;
    USE SIGNAL ;
    ANTENNADIFFAREA 0.708600 ;
    PORT
      LAYER Metal3 ;
        RECT 238.640 173.260 239.040 173.660 ;
    END
  END FrameData_O[7]
  PIN FrameData_O[8]
    DIRECTION OUTPUT ;
    USE SIGNAL ;
    ANTENNADIFFAREA 0.708600 ;
    PORT
      LAYER Metal3 ;
        RECT 238.640 174.940 239.040 175.340 ;
    END
  END FrameData_O[8]
  PIN FrameData_O[9]
    DIRECTION OUTPUT ;
    USE SIGNAL ;
    ANTENNADIFFAREA 0.708600 ;
    PORT
      LAYER Metal3 ;
        RECT 238.640 176.620 239.040 177.020 ;
    END
  END FrameData_O[9]
  PIN FrameStrobe[0]
    DIRECTION INPUT ;
    USE SIGNAL ;
    ANTENNAGATEAREA 6.753500 ;
    PORT
      LAYER Metal2 ;
        RECT 160.600 0.000 161.000 0.400 ;
    END
  END FrameStrobe[0]
  PIN FrameStrobe[10]
    DIRECTION INPUT ;
    USE SIGNAL ;
    ANTENNAGATEAREA 6.753500 ;
    PORT
      LAYER Metal2 ;
        RECT 170.200 0.000 170.600 0.400 ;
    END
  END FrameStrobe[10]
  PIN FrameStrobe[11]
    DIRECTION INPUT ;
    USE SIGNAL ;
    ANTENNAGATEAREA 6.753500 ;
    PORT
      LAYER Metal2 ;
        RECT 171.160 0.000 171.560 0.400 ;
    END
  END FrameStrobe[11]
  PIN FrameStrobe[12]
    DIRECTION INPUT ;
    USE SIGNAL ;
    ANTENNAGATEAREA 6.342700 ;
    PORT
      LAYER Metal2 ;
        RECT 172.120 0.000 172.520 0.400 ;
    END
  END FrameStrobe[12]
  PIN FrameStrobe[13]
    DIRECTION INPUT ;
    USE SIGNAL ;
    ANTENNAGATEAREA 0.789100 ;
    ANTENNADIFFAREA 2.015400 ;
    PORT
      LAYER Metal2 ;
        RECT 173.080 0.000 173.480 0.400 ;
    END
  END FrameStrobe[13]
  PIN FrameStrobe[14]
    DIRECTION INPUT ;
    USE SIGNAL ;
    ANTENNAGATEAREA 0.789100 ;
    ANTENNADIFFAREA 2.015400 ;
    PORT
      LAYER Metal2 ;
        RECT 174.040 0.000 174.440 0.400 ;
    END
  END FrameStrobe[14]
  PIN FrameStrobe[15]
    DIRECTION INPUT ;
    USE SIGNAL ;
    ANTENNAGATEAREA 0.789100 ;
    ANTENNADIFFAREA 2.015400 ;
    PORT
      LAYER Metal2 ;
        RECT 175.000 0.000 175.400 0.400 ;
    END
  END FrameStrobe[15]
  PIN FrameStrobe[16]
    DIRECTION INPUT ;
    USE SIGNAL ;
    ANTENNAGATEAREA 0.180700 ;
    PORT
      LAYER Metal2 ;
        RECT 175.960 0.000 176.360 0.400 ;
    END
  END FrameStrobe[16]
  PIN FrameStrobe[17]
    DIRECTION INPUT ;
    USE SIGNAL ;
    ANTENNAGATEAREA 0.180700 ;
    PORT
      LAYER Metal2 ;
        RECT 176.920 0.000 177.320 0.400 ;
    END
  END FrameStrobe[17]
  PIN FrameStrobe[18]
    DIRECTION INPUT ;
    USE SIGNAL ;
    ANTENNAGATEAREA 0.789100 ;
    ANTENNADIFFAREA 2.015400 ;
    PORT
      LAYER Metal2 ;
        RECT 177.880 0.000 178.280 0.400 ;
    END
  END FrameStrobe[18]
  PIN FrameStrobe[19]
    DIRECTION INPUT ;
    USE SIGNAL ;
    ANTENNAGATEAREA 0.789100 ;
    ANTENNADIFFAREA 2.015400 ;
    PORT
      LAYER Metal2 ;
        RECT 178.840 0.000 179.240 0.400 ;
    END
  END FrameStrobe[19]
  PIN FrameStrobe[1]
    DIRECTION INPUT ;
    USE SIGNAL ;
    ANTENNAGATEAREA 6.753500 ;
    PORT
      LAYER Metal2 ;
        RECT 161.560 0.000 161.960 0.400 ;
    END
  END FrameStrobe[1]
  PIN FrameStrobe[2]
    DIRECTION INPUT ;
    USE SIGNAL ;
    ANTENNAGATEAREA 6.753500 ;
    PORT
      LAYER Metal2 ;
        RECT 162.520 0.000 162.920 0.400 ;
    END
  END FrameStrobe[2]
  PIN FrameStrobe[3]
    DIRECTION INPUT ;
    USE SIGNAL ;
    ANTENNAGATEAREA 6.753500 ;
    PORT
      LAYER Metal2 ;
        RECT 163.480 0.000 163.880 0.400 ;
    END
  END FrameStrobe[3]
  PIN FrameStrobe[4]
    DIRECTION INPUT ;
    USE SIGNAL ;
    ANTENNAGATEAREA 6.753500 ;
    PORT
      LAYER Metal2 ;
        RECT 164.440 0.000 164.840 0.400 ;
    END
  END FrameStrobe[4]
  PIN FrameStrobe[5]
    DIRECTION INPUT ;
    USE SIGNAL ;
    ANTENNAGATEAREA 6.753500 ;
    PORT
      LAYER Metal2 ;
        RECT 165.400 0.000 165.800 0.400 ;
    END
  END FrameStrobe[5]
  PIN FrameStrobe[6]
    DIRECTION INPUT ;
    USE SIGNAL ;
    ANTENNAGATEAREA 6.753500 ;
    PORT
      LAYER Metal2 ;
        RECT 166.360 0.000 166.760 0.400 ;
    END
  END FrameStrobe[6]
  PIN FrameStrobe[7]
    DIRECTION INPUT ;
    USE SIGNAL ;
    ANTENNAGATEAREA 6.753500 ;
    PORT
      LAYER Metal2 ;
        RECT 167.320 0.000 167.720 0.400 ;
    END
  END FrameStrobe[7]
  PIN FrameStrobe[8]
    DIRECTION INPUT ;
    USE SIGNAL ;
    ANTENNAGATEAREA 6.753500 ;
    PORT
      LAYER Metal2 ;
        RECT 168.280 0.000 168.680 0.400 ;
    END
  END FrameStrobe[8]
  PIN FrameStrobe[9]
    DIRECTION INPUT ;
    USE SIGNAL ;
    ANTENNAGATEAREA 6.753500 ;
    PORT
      LAYER Metal2 ;
        RECT 169.240 0.000 169.640 0.400 ;
    END
  END FrameStrobe[9]
  PIN FrameStrobe_O[0]
    DIRECTION OUTPUT ;
    USE SIGNAL ;
    ANTENNADIFFAREA 0.708600 ;
    PORT
      LAYER Metal2 ;
        RECT 160.600 215.060 161.000 215.460 ;
    END
  END FrameStrobe_O[0]
  PIN FrameStrobe_O[10]
    DIRECTION OUTPUT ;
    USE SIGNAL ;
    ANTENNADIFFAREA 0.708600 ;
    PORT
      LAYER Metal2 ;
        RECT 170.200 215.060 170.600 215.460 ;
    END
  END FrameStrobe_O[10]
  PIN FrameStrobe_O[11]
    DIRECTION OUTPUT ;
    USE SIGNAL ;
    ANTENNADIFFAREA 0.708600 ;
    PORT
      LAYER Metal2 ;
        RECT 171.160 215.060 171.560 215.460 ;
    END
  END FrameStrobe_O[11]
  PIN FrameStrobe_O[12]
    DIRECTION OUTPUT ;
    USE SIGNAL ;
    ANTENNADIFFAREA 0.708600 ;
    PORT
      LAYER Metal2 ;
        RECT 172.120 215.060 172.520 215.460 ;
    END
  END FrameStrobe_O[12]
  PIN FrameStrobe_O[13]
    DIRECTION OUTPUT ;
    USE SIGNAL ;
    ANTENNADIFFAREA 0.708600 ;
    PORT
      LAYER Metal2 ;
        RECT 173.080 215.060 173.480 215.460 ;
    END
  END FrameStrobe_O[13]
  PIN FrameStrobe_O[14]
    DIRECTION OUTPUT ;
    USE SIGNAL ;
    ANTENNADIFFAREA 0.708600 ;
    PORT
      LAYER Metal2 ;
        RECT 174.040 215.060 174.440 215.460 ;
    END
  END FrameStrobe_O[14]
  PIN FrameStrobe_O[15]
    DIRECTION OUTPUT ;
    USE SIGNAL ;
    ANTENNADIFFAREA 0.708600 ;
    PORT
      LAYER Metal2 ;
        RECT 175.000 215.060 175.400 215.460 ;
    END
  END FrameStrobe_O[15]
  PIN FrameStrobe_O[16]
    DIRECTION OUTPUT ;
    USE SIGNAL ;
    ANTENNADIFFAREA 0.708600 ;
    PORT
      LAYER Metal2 ;
        RECT 175.960 215.060 176.360 215.460 ;
    END
  END FrameStrobe_O[16]
  PIN FrameStrobe_O[17]
    DIRECTION OUTPUT ;
    USE SIGNAL ;
    ANTENNADIFFAREA 0.708600 ;
    PORT
      LAYER Metal2 ;
        RECT 176.920 215.060 177.320 215.460 ;
    END
  END FrameStrobe_O[17]
  PIN FrameStrobe_O[18]
    DIRECTION OUTPUT ;
    USE SIGNAL ;
    ANTENNADIFFAREA 0.708600 ;
    PORT
      LAYER Metal2 ;
        RECT 177.880 215.060 178.280 215.460 ;
    END
  END FrameStrobe_O[18]
  PIN FrameStrobe_O[19]
    DIRECTION OUTPUT ;
    USE SIGNAL ;
    ANTENNADIFFAREA 0.708600 ;
    PORT
      LAYER Metal2 ;
        RECT 178.840 215.060 179.240 215.460 ;
    END
  END FrameStrobe_O[19]
  PIN FrameStrobe_O[1]
    DIRECTION OUTPUT ;
    USE SIGNAL ;
    ANTENNADIFFAREA 0.708600 ;
    PORT
      LAYER Metal2 ;
        RECT 161.560 215.060 161.960 215.460 ;
    END
  END FrameStrobe_O[1]
  PIN FrameStrobe_O[2]
    DIRECTION OUTPUT ;
    USE SIGNAL ;
    ANTENNADIFFAREA 0.708600 ;
    PORT
      LAYER Metal2 ;
        RECT 162.520 215.060 162.920 215.460 ;
    END
  END FrameStrobe_O[2]
  PIN FrameStrobe_O[3]
    DIRECTION OUTPUT ;
    USE SIGNAL ;
    ANTENNADIFFAREA 0.708600 ;
    PORT
      LAYER Metal2 ;
        RECT 163.480 215.060 163.880 215.460 ;
    END
  END FrameStrobe_O[3]
  PIN FrameStrobe_O[4]
    DIRECTION OUTPUT ;
    USE SIGNAL ;
    ANTENNADIFFAREA 0.708600 ;
    PORT
      LAYER Metal2 ;
        RECT 164.440 215.060 164.840 215.460 ;
    END
  END FrameStrobe_O[4]
  PIN FrameStrobe_O[5]
    DIRECTION OUTPUT ;
    USE SIGNAL ;
    ANTENNADIFFAREA 0.708600 ;
    PORT
      LAYER Metal2 ;
        RECT 165.400 215.060 165.800 215.460 ;
    END
  END FrameStrobe_O[5]
  PIN FrameStrobe_O[6]
    DIRECTION OUTPUT ;
    USE SIGNAL ;
    ANTENNADIFFAREA 0.708600 ;
    PORT
      LAYER Metal2 ;
        RECT 166.360 215.060 166.760 215.460 ;
    END
  END FrameStrobe_O[6]
  PIN FrameStrobe_O[7]
    DIRECTION OUTPUT ;
    USE SIGNAL ;
    ANTENNADIFFAREA 0.708600 ;
    PORT
      LAYER Metal2 ;
        RECT 167.320 215.060 167.720 215.460 ;
    END
  END FrameStrobe_O[7]
  PIN FrameStrobe_O[8]
    DIRECTION OUTPUT ;
    USE SIGNAL ;
    ANTENNADIFFAREA 0.708600 ;
    PORT
      LAYER Metal2 ;
        RECT 168.280 215.060 168.680 215.460 ;
    END
  END FrameStrobe_O[8]
  PIN FrameStrobe_O[9]
    DIRECTION OUTPUT ;
    USE SIGNAL ;
    ANTENNADIFFAREA 0.708600 ;
    PORT
      LAYER Metal2 ;
        RECT 169.240 215.060 169.640 215.460 ;
    END
  END FrameStrobe_O[9]
  PIN N1BEG[0]
    DIRECTION OUTPUT ;
    USE SIGNAL ;
    ANTENNADIFFAREA 0.708600 ;
    PORT
      LAYER Metal2 ;
        RECT 59.800 215.060 60.200 215.460 ;
    END
  END N1BEG[0]
  PIN N1BEG[1]
    DIRECTION OUTPUT ;
    USE SIGNAL ;
    ANTENNADIFFAREA 0.708600 ;
    PORT
      LAYER Metal2 ;
        RECT 60.760 215.060 61.160 215.460 ;
    END
  END N1BEG[1]
  PIN N1BEG[2]
    DIRECTION OUTPUT ;
    USE SIGNAL ;
    ANTENNADIFFAREA 0.708600 ;
    PORT
      LAYER Metal2 ;
        RECT 61.720 215.060 62.120 215.460 ;
    END
  END N1BEG[2]
  PIN N1BEG[3]
    DIRECTION OUTPUT ;
    USE SIGNAL ;
    ANTENNADIFFAREA 0.708600 ;
    PORT
      LAYER Metal2 ;
        RECT 62.680 215.060 63.080 215.460 ;
    END
  END N1BEG[3]
  PIN N1END[0]
    DIRECTION INPUT ;
    USE SIGNAL ;
    ANTENNAGATEAREA 2.112500 ;
    PORT
      LAYER Metal2 ;
        RECT 59.800 0.000 60.200 0.400 ;
    END
  END N1END[0]
  PIN N1END[1]
    DIRECTION INPUT ;
    USE SIGNAL ;
    ANTENNAGATEAREA 2.132000 ;
    PORT
      LAYER Metal2 ;
        RECT 60.760 0.000 61.160 0.400 ;
    END
  END N1END[1]
  PIN N1END[2]
    DIRECTION INPUT ;
    USE SIGNAL ;
    ANTENNAGATEAREA 2.145000 ;
    PORT
      LAYER Metal2 ;
        RECT 61.720 0.000 62.120 0.400 ;
    END
  END N1END[2]
  PIN N1END[3]
    DIRECTION INPUT ;
    USE SIGNAL ;
    ANTENNAGATEAREA 2.132000 ;
    PORT
      LAYER Metal2 ;
        RECT 62.680 0.000 63.080 0.400 ;
    END
  END N1END[3]
  PIN N2BEG[0]
    DIRECTION OUTPUT ;
    USE SIGNAL ;
    ANTENNADIFFAREA 0.708600 ;
    PORT
      LAYER Metal2 ;
        RECT 63.640 215.060 64.040 215.460 ;
    END
  END N2BEG[0]
  PIN N2BEG[1]
    DIRECTION OUTPUT ;
    USE SIGNAL ;
    ANTENNADIFFAREA 0.708600 ;
    PORT
      LAYER Metal2 ;
        RECT 64.600 215.060 65.000 215.460 ;
    END
  END N2BEG[1]
  PIN N2BEG[2]
    DIRECTION OUTPUT ;
    USE SIGNAL ;
    ANTENNADIFFAREA 0.708600 ;
    PORT
      LAYER Metal2 ;
        RECT 65.560 215.060 65.960 215.460 ;
    END
  END N2BEG[2]
  PIN N2BEG[3]
    DIRECTION OUTPUT ;
    USE SIGNAL ;
    ANTENNADIFFAREA 0.708600 ;
    PORT
      LAYER Metal2 ;
        RECT 66.520 215.060 66.920 215.460 ;
    END
  END N2BEG[3]
  PIN N2BEG[4]
    DIRECTION OUTPUT ;
    USE SIGNAL ;
    ANTENNADIFFAREA 0.708600 ;
    PORT
      LAYER Metal2 ;
        RECT 67.480 215.060 67.880 215.460 ;
    END
  END N2BEG[4]
  PIN N2BEG[5]
    DIRECTION OUTPUT ;
    USE SIGNAL ;
    ANTENNADIFFAREA 0.708600 ;
    PORT
      LAYER Metal2 ;
        RECT 68.440 215.060 68.840 215.460 ;
    END
  END N2BEG[5]
  PIN N2BEG[6]
    DIRECTION OUTPUT ;
    USE SIGNAL ;
    ANTENNADIFFAREA 0.708600 ;
    PORT
      LAYER Metal2 ;
        RECT 69.400 215.060 69.800 215.460 ;
    END
  END N2BEG[6]
  PIN N2BEG[7]
    DIRECTION OUTPUT ;
    USE SIGNAL ;
    ANTENNADIFFAREA 0.708600 ;
    PORT
      LAYER Metal2 ;
        RECT 70.360 215.060 70.760 215.460 ;
    END
  END N2BEG[7]
  PIN N2BEGb[0]
    DIRECTION OUTPUT ;
    USE SIGNAL ;
    ANTENNADIFFAREA 0.708600 ;
    PORT
      LAYER Metal2 ;
        RECT 71.320 215.060 71.720 215.460 ;
    END
  END N2BEGb[0]
  PIN N2BEGb[1]
    DIRECTION OUTPUT ;
    USE SIGNAL ;
    ANTENNADIFFAREA 0.708600 ;
    PORT
      LAYER Metal2 ;
        RECT 72.280 215.060 72.680 215.460 ;
    END
  END N2BEGb[1]
  PIN N2BEGb[2]
    DIRECTION OUTPUT ;
    USE SIGNAL ;
    ANTENNADIFFAREA 0.708600 ;
    PORT
      LAYER Metal2 ;
        RECT 73.240 215.060 73.640 215.460 ;
    END
  END N2BEGb[2]
  PIN N2BEGb[3]
    DIRECTION OUTPUT ;
    USE SIGNAL ;
    ANTENNADIFFAREA 0.708600 ;
    PORT
      LAYER Metal2 ;
        RECT 74.200 215.060 74.600 215.460 ;
    END
  END N2BEGb[3]
  PIN N2BEGb[4]
    DIRECTION OUTPUT ;
    USE SIGNAL ;
    ANTENNADIFFAREA 0.708600 ;
    PORT
      LAYER Metal2 ;
        RECT 75.160 215.060 75.560 215.460 ;
    END
  END N2BEGb[4]
  PIN N2BEGb[5]
    DIRECTION OUTPUT ;
    USE SIGNAL ;
    ANTENNADIFFAREA 0.708600 ;
    PORT
      LAYER Metal2 ;
        RECT 76.120 215.060 76.520 215.460 ;
    END
  END N2BEGb[5]
  PIN N2BEGb[6]
    DIRECTION OUTPUT ;
    USE SIGNAL ;
    ANTENNADIFFAREA 0.708600 ;
    PORT
      LAYER Metal2 ;
        RECT 77.080 215.060 77.480 215.460 ;
    END
  END N2BEGb[6]
  PIN N2BEGb[7]
    DIRECTION OUTPUT ;
    USE SIGNAL ;
    ANTENNADIFFAREA 0.708600 ;
    PORT
      LAYER Metal2 ;
        RECT 78.040 215.060 78.440 215.460 ;
    END
  END N2BEGb[7]
  PIN N2END[0]
    DIRECTION INPUT ;
    USE SIGNAL ;
    ANTENNAGATEAREA 1.731600 ;
    PORT
      LAYER Metal2 ;
        RECT 71.320 0.000 71.720 0.400 ;
    END
  END N2END[0]
  PIN N2END[1]
    DIRECTION INPUT ;
    USE SIGNAL ;
    ANTENNAGATEAREA 1.521000 ;
    PORT
      LAYER Metal2 ;
        RECT 72.280 0.000 72.680 0.400 ;
    END
  END N2END[1]
  PIN N2END[2]
    DIRECTION INPUT ;
    USE SIGNAL ;
    ANTENNAGATEAREA 1.488500 ;
    PORT
      LAYER Metal2 ;
        RECT 73.240 0.000 73.640 0.400 ;
    END
  END N2END[2]
  PIN N2END[3]
    DIRECTION INPUT ;
    USE SIGNAL ;
    ANTENNAGATEAREA 1.771400 ;
    PORT
      LAYER Metal2 ;
        RECT 74.200 0.000 74.600 0.400 ;
    END
  END N2END[3]
  PIN N2END[4]
    DIRECTION INPUT ;
    USE SIGNAL ;
    ANTENNAGATEAREA 1.292200 ;
    PORT
      LAYER Metal2 ;
        RECT 75.160 0.000 75.560 0.400 ;
    END
  END N2END[4]
  PIN N2END[5]
    DIRECTION INPUT ;
    USE SIGNAL ;
    ANTENNAGATEAREA 1.066000 ;
    PORT
      LAYER Metal2 ;
        RECT 76.120 0.000 76.520 0.400 ;
    END
  END N2END[5]
  PIN N2END[6]
    DIRECTION INPUT ;
    USE SIGNAL ;
    ANTENNAGATEAREA 1.079000 ;
    PORT
      LAYER Metal2 ;
        RECT 77.080 0.000 77.480 0.400 ;
    END
  END N2END[6]
  PIN N2END[7]
    DIRECTION INPUT ;
    USE SIGNAL ;
    ANTENNAGATEAREA 1.279200 ;
    PORT
      LAYER Metal2 ;
        RECT 78.040 0.000 78.440 0.400 ;
    END
  END N2END[7]
  PIN N2MID[0]
    DIRECTION INPUT ;
    USE SIGNAL ;
    ANTENNAGATEAREA 3.919500 ;
    ANTENNADIFFAREA 10.077000 ;
    PORT
      LAYER Metal2 ;
        RECT 63.640 0.000 64.040 0.400 ;
    END
  END N2MID[0]
  PIN N2MID[1]
    DIRECTION INPUT ;
    USE SIGNAL ;
    ANTENNAGATEAREA 1.112300 ;
    PORT
      LAYER Metal2 ;
        RECT 64.600 0.000 65.000 0.400 ;
    END
  END N2MID[1]
  PIN N2MID[2]
    DIRECTION INPUT ;
    USE SIGNAL ;
    ANTENNAGATEAREA 0.820300 ;
    PORT
      LAYER Metal2 ;
        RECT 65.560 0.000 65.960 0.400 ;
    END
  END N2MID[2]
  PIN N2MID[3]
    DIRECTION INPUT ;
    USE SIGNAL ;
    ANTENNAGATEAREA 1.033500 ;
    PORT
      LAYER Metal2 ;
        RECT 66.520 0.000 66.920 0.400 ;
    END
  END N2MID[3]
  PIN N2MID[4]
    DIRECTION INPUT ;
    USE SIGNAL ;
    ANTENNAGATEAREA 0.820300 ;
    PORT
      LAYER Metal2 ;
        RECT 67.480 0.000 67.880 0.400 ;
    END
  END N2MID[4]
  PIN N2MID[5]
    DIRECTION INPUT ;
    USE SIGNAL ;
    ANTENNAGATEAREA 1.033500 ;
    PORT
      LAYER Metal2 ;
        RECT 68.440 0.000 68.840 0.400 ;
    END
  END N2MID[5]
  PIN N2MID[6]
    DIRECTION INPUT ;
    USE SIGNAL ;
    ANTENNAGATEAREA 0.848900 ;
    PORT
      LAYER Metal2 ;
        RECT 69.400 0.000 69.800 0.400 ;
    END
  END N2MID[6]
  PIN N2MID[7]
    DIRECTION INPUT ;
    USE SIGNAL ;
    ANTENNAGATEAREA 16.309299 ;
    ANTENNADIFFAREA 50.384998 ;
    PORT
      LAYER Metal2 ;
        RECT 70.360 0.000 70.760 0.400 ;
    END
  END N2MID[7]
  PIN N4BEG[0]
    DIRECTION OUTPUT ;
    USE SIGNAL ;
    ANTENNADIFFAREA 0.708600 ;
    PORT
      LAYER Metal2 ;
        RECT 79.000 215.060 79.400 215.460 ;
    END
  END N4BEG[0]
  PIN N4BEG[10]
    DIRECTION OUTPUT ;
    USE SIGNAL ;
    ANTENNADIFFAREA 0.708600 ;
    PORT
      LAYER Metal2 ;
        RECT 88.600 215.060 89.000 215.460 ;
    END
  END N4BEG[10]
  PIN N4BEG[11]
    DIRECTION OUTPUT ;
    USE SIGNAL ;
    ANTENNADIFFAREA 0.708600 ;
    PORT
      LAYER Metal2 ;
        RECT 89.560 215.060 89.960 215.460 ;
    END
  END N4BEG[11]
  PIN N4BEG[12]
    DIRECTION OUTPUT ;
    USE SIGNAL ;
    ANTENNADIFFAREA 0.708600 ;
    PORT
      LAYER Metal2 ;
        RECT 90.520 215.060 90.920 215.460 ;
    END
  END N4BEG[12]
  PIN N4BEG[13]
    DIRECTION OUTPUT ;
    USE SIGNAL ;
    ANTENNADIFFAREA 0.708600 ;
    PORT
      LAYER Metal2 ;
        RECT 91.480 215.060 91.880 215.460 ;
    END
  END N4BEG[13]
  PIN N4BEG[14]
    DIRECTION OUTPUT ;
    USE SIGNAL ;
    ANTENNADIFFAREA 0.708600 ;
    PORT
      LAYER Metal2 ;
        RECT 92.440 215.060 92.840 215.460 ;
    END
  END N4BEG[14]
  PIN N4BEG[15]
    DIRECTION OUTPUT ;
    USE SIGNAL ;
    ANTENNADIFFAREA 0.708600 ;
    PORT
      LAYER Metal2 ;
        RECT 93.400 215.060 93.800 215.460 ;
    END
  END N4BEG[15]
  PIN N4BEG[1]
    DIRECTION OUTPUT ;
    USE SIGNAL ;
    ANTENNADIFFAREA 0.708600 ;
    PORT
      LAYER Metal2 ;
        RECT 79.960 215.060 80.360 215.460 ;
    END
  END N4BEG[1]
  PIN N4BEG[2]
    DIRECTION OUTPUT ;
    USE SIGNAL ;
    ANTENNADIFFAREA 0.708600 ;
    PORT
      LAYER Metal2 ;
        RECT 80.920 215.060 81.320 215.460 ;
    END
  END N4BEG[2]
  PIN N4BEG[3]
    DIRECTION OUTPUT ;
    USE SIGNAL ;
    ANTENNADIFFAREA 0.708600 ;
    PORT
      LAYER Metal2 ;
        RECT 81.880 215.060 82.280 215.460 ;
    END
  END N4BEG[3]
  PIN N4BEG[4]
    DIRECTION OUTPUT ;
    USE SIGNAL ;
    ANTENNADIFFAREA 0.708600 ;
    PORT
      LAYER Metal2 ;
        RECT 82.840 215.060 83.240 215.460 ;
    END
  END N4BEG[4]
  PIN N4BEG[5]
    DIRECTION OUTPUT ;
    USE SIGNAL ;
    ANTENNADIFFAREA 0.708600 ;
    PORT
      LAYER Metal2 ;
        RECT 83.800 215.060 84.200 215.460 ;
    END
  END N4BEG[5]
  PIN N4BEG[6]
    DIRECTION OUTPUT ;
    USE SIGNAL ;
    ANTENNADIFFAREA 0.708600 ;
    PORT
      LAYER Metal2 ;
        RECT 84.760 215.060 85.160 215.460 ;
    END
  END N4BEG[6]
  PIN N4BEG[7]
    DIRECTION OUTPUT ;
    USE SIGNAL ;
    ANTENNADIFFAREA 0.708600 ;
    PORT
      LAYER Metal2 ;
        RECT 85.720 215.060 86.120 215.460 ;
    END
  END N4BEG[7]
  PIN N4BEG[8]
    DIRECTION OUTPUT ;
    USE SIGNAL ;
    ANTENNADIFFAREA 0.708600 ;
    PORT
      LAYER Metal2 ;
        RECT 86.680 215.060 87.080 215.460 ;
    END
  END N4BEG[8]
  PIN N4BEG[9]
    DIRECTION OUTPUT ;
    USE SIGNAL ;
    ANTENNADIFFAREA 0.708600 ;
    PORT
      LAYER Metal2 ;
        RECT 87.640 215.060 88.040 215.460 ;
    END
  END N4BEG[9]
  PIN N4END[0]
    DIRECTION INPUT ;
    USE SIGNAL ;
    ANTENNAGATEAREA 1.033500 ;
    PORT
      LAYER Metal2 ;
        RECT 79.000 0.000 79.400 0.400 ;
    END
  END N4END[0]
  PIN N4END[10]
    DIRECTION INPUT ;
    USE SIGNAL ;
    ANTENNAGATEAREA 0.180700 ;
    PORT
      LAYER Metal2 ;
        RECT 88.600 0.000 89.000 0.400 ;
    END
  END N4END[10]
  PIN N4END[11]
    DIRECTION INPUT ;
    USE SIGNAL ;
    ANTENNAGATEAREA 0.180700 ;
    PORT
      LAYER Metal2 ;
        RECT 89.560 0.000 89.960 0.400 ;
    END
  END N4END[11]
  PIN N4END[12]
    DIRECTION INPUT ;
    USE SIGNAL ;
    ANTENNAGATEAREA 0.180700 ;
    PORT
      LAYER Metal2 ;
        RECT 90.520 0.000 90.920 0.400 ;
    END
  END N4END[12]
  PIN N4END[13]
    DIRECTION INPUT ;
    USE SIGNAL ;
    ANTENNAGATEAREA 0.180700 ;
    PORT
      LAYER Metal2 ;
        RECT 91.480 0.000 91.880 0.400 ;
    END
  END N4END[13]
  PIN N4END[14]
    DIRECTION INPUT ;
    USE SIGNAL ;
    ANTENNAGATEAREA 0.180700 ;
    PORT
      LAYER Metal2 ;
        RECT 92.440 0.000 92.840 0.400 ;
    END
  END N4END[14]
  PIN N4END[15]
    DIRECTION INPUT ;
    USE SIGNAL ;
    ANTENNAGATEAREA 0.180700 ;
    PORT
      LAYER Metal2 ;
        RECT 93.400 0.000 93.800 0.400 ;
    END
  END N4END[15]
  PIN N4END[1]
    DIRECTION INPUT ;
    USE SIGNAL ;
    ANTENNAGATEAREA 1.066000 ;
    PORT
      LAYER Metal2 ;
        RECT 79.960 0.000 80.360 0.400 ;
    END
  END N4END[1]
  PIN N4END[2]
    DIRECTION INPUT ;
    USE SIGNAL ;
    ANTENNAGATEAREA 1.001000 ;
    PORT
      LAYER Metal2 ;
        RECT 80.920 0.000 81.320 0.400 ;
    END
  END N4END[2]
  PIN N4END[3]
    DIRECTION INPUT ;
    USE SIGNAL ;
    ANTENNAGATEAREA 1.001000 ;
    PORT
      LAYER Metal2 ;
        RECT 81.880 0.000 82.280 0.400 ;
    END
  END N4END[3]
  PIN N4END[4]
    DIRECTION INPUT ;
    USE SIGNAL ;
    ANTENNAGATEAREA 0.180700 ;
    PORT
      LAYER Metal2 ;
        RECT 82.840 0.000 83.240 0.400 ;
    END
  END N4END[4]
  PIN N4END[5]
    DIRECTION INPUT ;
    USE SIGNAL ;
    ANTENNAGATEAREA 0.180700 ;
    PORT
      LAYER Metal2 ;
        RECT 83.800 0.000 84.200 0.400 ;
    END
  END N4END[5]
  PIN N4END[6]
    DIRECTION INPUT ;
    USE SIGNAL ;
    ANTENNAGATEAREA 0.180700 ;
    PORT
      LAYER Metal2 ;
        RECT 84.760 0.000 85.160 0.400 ;
    END
  END N4END[6]
  PIN N4END[7]
    DIRECTION INPUT ;
    USE SIGNAL ;
    ANTENNAGATEAREA 0.180700 ;
    PORT
      LAYER Metal2 ;
        RECT 85.720 0.000 86.120 0.400 ;
    END
  END N4END[7]
  PIN N4END[8]
    DIRECTION INPUT ;
    USE SIGNAL ;
    ANTENNAGATEAREA 0.180700 ;
    PORT
      LAYER Metal2 ;
        RECT 86.680 0.000 87.080 0.400 ;
    END
  END N4END[8]
  PIN N4END[9]
    DIRECTION INPUT ;
    USE SIGNAL ;
    ANTENNAGATEAREA 0.180700 ;
    PORT
      LAYER Metal2 ;
        RECT 87.640 0.000 88.040 0.400 ;
    END
  END N4END[9]
  PIN NN4BEG[0]
    DIRECTION OUTPUT ;
    USE SIGNAL ;
    ANTENNADIFFAREA 0.708600 ;
    PORT
      LAYER Metal2 ;
        RECT 94.360 215.060 94.760 215.460 ;
    END
  END NN4BEG[0]
  PIN NN4BEG[10]
    DIRECTION OUTPUT ;
    USE SIGNAL ;
    ANTENNADIFFAREA 0.708600 ;
    PORT
      LAYER Metal2 ;
        RECT 103.960 215.060 104.360 215.460 ;
    END
  END NN4BEG[10]
  PIN NN4BEG[11]
    DIRECTION OUTPUT ;
    USE SIGNAL ;
    ANTENNADIFFAREA 0.708600 ;
    PORT
      LAYER Metal2 ;
        RECT 104.920 215.060 105.320 215.460 ;
    END
  END NN4BEG[11]
  PIN NN4BEG[12]
    DIRECTION OUTPUT ;
    USE SIGNAL ;
    ANTENNADIFFAREA 0.708600 ;
    PORT
      LAYER Metal2 ;
        RECT 105.880 215.060 106.280 215.460 ;
    END
  END NN4BEG[12]
  PIN NN4BEG[13]
    DIRECTION OUTPUT ;
    USE SIGNAL ;
    ANTENNADIFFAREA 0.708600 ;
    PORT
      LAYER Metal2 ;
        RECT 106.840 215.060 107.240 215.460 ;
    END
  END NN4BEG[13]
  PIN NN4BEG[14]
    DIRECTION OUTPUT ;
    USE SIGNAL ;
    ANTENNADIFFAREA 0.708600 ;
    PORT
      LAYER Metal2 ;
        RECT 107.800 215.060 108.200 215.460 ;
    END
  END NN4BEG[14]
  PIN NN4BEG[15]
    DIRECTION OUTPUT ;
    USE SIGNAL ;
    ANTENNADIFFAREA 0.708600 ;
    PORT
      LAYER Metal2 ;
        RECT 108.760 215.060 109.160 215.460 ;
    END
  END NN4BEG[15]
  PIN NN4BEG[1]
    DIRECTION OUTPUT ;
    USE SIGNAL ;
    ANTENNADIFFAREA 0.708600 ;
    PORT
      LAYER Metal2 ;
        RECT 95.320 215.060 95.720 215.460 ;
    END
  END NN4BEG[1]
  PIN NN4BEG[2]
    DIRECTION OUTPUT ;
    USE SIGNAL ;
    ANTENNADIFFAREA 0.708600 ;
    PORT
      LAYER Metal2 ;
        RECT 96.280 215.060 96.680 215.460 ;
    END
  END NN4BEG[2]
  PIN NN4BEG[3]
    DIRECTION OUTPUT ;
    USE SIGNAL ;
    ANTENNADIFFAREA 0.708600 ;
    PORT
      LAYER Metal2 ;
        RECT 97.240 215.060 97.640 215.460 ;
    END
  END NN4BEG[3]
  PIN NN4BEG[4]
    DIRECTION OUTPUT ;
    USE SIGNAL ;
    ANTENNADIFFAREA 0.708600 ;
    PORT
      LAYER Metal2 ;
        RECT 98.200 215.060 98.600 215.460 ;
    END
  END NN4BEG[4]
  PIN NN4BEG[5]
    DIRECTION OUTPUT ;
    USE SIGNAL ;
    ANTENNADIFFAREA 0.708600 ;
    PORT
      LAYER Metal2 ;
        RECT 99.160 215.060 99.560 215.460 ;
    END
  END NN4BEG[5]
  PIN NN4BEG[6]
    DIRECTION OUTPUT ;
    USE SIGNAL ;
    ANTENNADIFFAREA 0.708600 ;
    PORT
      LAYER Metal2 ;
        RECT 100.120 215.060 100.520 215.460 ;
    END
  END NN4BEG[6]
  PIN NN4BEG[7]
    DIRECTION OUTPUT ;
    USE SIGNAL ;
    ANTENNADIFFAREA 0.708600 ;
    PORT
      LAYER Metal2 ;
        RECT 101.080 215.060 101.480 215.460 ;
    END
  END NN4BEG[7]
  PIN NN4BEG[8]
    DIRECTION OUTPUT ;
    USE SIGNAL ;
    ANTENNADIFFAREA 0.708600 ;
    PORT
      LAYER Metal2 ;
        RECT 102.040 215.060 102.440 215.460 ;
    END
  END NN4BEG[8]
  PIN NN4BEG[9]
    DIRECTION OUTPUT ;
    USE SIGNAL ;
    ANTENNADIFFAREA 0.708600 ;
    PORT
      LAYER Metal2 ;
        RECT 103.000 215.060 103.400 215.460 ;
    END
  END NN4BEG[9]
  PIN NN4END[0]
    DIRECTION INPUT ;
    USE SIGNAL ;
    ANTENNAGATEAREA 1.107600 ;
    PORT
      LAYER Metal2 ;
        RECT 94.360 0.000 94.760 0.400 ;
    END
  END NN4END[0]
  PIN NN4END[10]
    DIRECTION INPUT ;
    USE SIGNAL ;
    ANTENNAGATEAREA 0.180700 ;
    PORT
      LAYER Metal2 ;
        RECT 103.960 0.000 104.360 0.400 ;
    END
  END NN4END[10]
  PIN NN4END[11]
    DIRECTION INPUT ;
    USE SIGNAL ;
    ANTENNAGATEAREA 0.180700 ;
    PORT
      LAYER Metal2 ;
        RECT 104.920 0.000 105.320 0.400 ;
    END
  END NN4END[11]
  PIN NN4END[12]
    DIRECTION INPUT ;
    USE SIGNAL ;
    ANTENNAGATEAREA 0.180700 ;
    PORT
      LAYER Metal2 ;
        RECT 105.880 0.000 106.280 0.400 ;
    END
  END NN4END[12]
  PIN NN4END[13]
    DIRECTION INPUT ;
    USE SIGNAL ;
    ANTENNAGATEAREA 0.180700 ;
    PORT
      LAYER Metal2 ;
        RECT 106.840 0.000 107.240 0.400 ;
    END
  END NN4END[13]
  PIN NN4END[14]
    DIRECTION INPUT ;
    USE SIGNAL ;
    ANTENNAGATEAREA 0.180700 ;
    PORT
      LAYER Metal2 ;
        RECT 107.800 0.000 108.200 0.400 ;
    END
  END NN4END[14]
  PIN NN4END[15]
    DIRECTION INPUT ;
    USE SIGNAL ;
    ANTENNAGATEAREA 0.180700 ;
    PORT
      LAYER Metal2 ;
        RECT 108.760 0.000 109.160 0.400 ;
    END
  END NN4END[15]
  PIN NN4END[1]
    DIRECTION INPUT ;
    USE SIGNAL ;
    ANTENNAGATEAREA 1.123200 ;
    PORT
      LAYER Metal2 ;
        RECT 95.320 0.000 95.720 0.400 ;
    END
  END NN4END[1]
  PIN NN4END[2]
    DIRECTION INPUT ;
    USE SIGNAL ;
    ANTENNAGATEAREA 1.033500 ;
    PORT
      LAYER Metal2 ;
        RECT 96.280 0.000 96.680 0.400 ;
    END
  END NN4END[2]
  PIN NN4END[3]
    DIRECTION INPUT ;
    USE SIGNAL ;
    ANTENNAGATEAREA 1.066000 ;
    PORT
      LAYER Metal2 ;
        RECT 97.240 0.000 97.640 0.400 ;
    END
  END NN4END[3]
  PIN NN4END[4]
    DIRECTION INPUT ;
    USE SIGNAL ;
    ANTENNAGATEAREA 0.180700 ;
    PORT
      LAYER Metal2 ;
        RECT 98.200 0.000 98.600 0.400 ;
    END
  END NN4END[4]
  PIN NN4END[5]
    DIRECTION INPUT ;
    USE SIGNAL ;
    ANTENNAGATEAREA 0.180700 ;
    PORT
      LAYER Metal2 ;
        RECT 99.160 0.000 99.560 0.400 ;
    END
  END NN4END[5]
  PIN NN4END[6]
    DIRECTION INPUT ;
    USE SIGNAL ;
    ANTENNAGATEAREA 0.180700 ;
    PORT
      LAYER Metal2 ;
        RECT 100.120 0.000 100.520 0.400 ;
    END
  END NN4END[6]
  PIN NN4END[7]
    DIRECTION INPUT ;
    USE SIGNAL ;
    ANTENNAGATEAREA 0.180700 ;
    PORT
      LAYER Metal2 ;
        RECT 101.080 0.000 101.480 0.400 ;
    END
  END NN4END[7]
  PIN NN4END[8]
    DIRECTION INPUT ;
    USE SIGNAL ;
    ANTENNAGATEAREA 0.180700 ;
    PORT
      LAYER Metal2 ;
        RECT 102.040 0.000 102.440 0.400 ;
    END
  END NN4END[8]
  PIN NN4END[9]
    DIRECTION INPUT ;
    USE SIGNAL ;
    ANTENNAGATEAREA 0.180700 ;
    PORT
      LAYER Metal2 ;
        RECT 103.000 0.000 103.400 0.400 ;
    END
  END NN4END[9]
  PIN S1BEG[0]
    DIRECTION OUTPUT ;
    USE SIGNAL ;
    ANTENNADIFFAREA 0.708600 ;
    PORT
      LAYER Metal2 ;
        RECT 109.720 0.000 110.120 0.400 ;
    END
  END S1BEG[0]
  PIN S1BEG[1]
    DIRECTION OUTPUT ;
    USE SIGNAL ;
    ANTENNADIFFAREA 0.708600 ;
    PORT
      LAYER Metal2 ;
        RECT 110.680 0.000 111.080 0.400 ;
    END
  END S1BEG[1]
  PIN S1BEG[2]
    DIRECTION OUTPUT ;
    USE SIGNAL ;
    ANTENNADIFFAREA 0.708600 ;
    PORT
      LAYER Metal2 ;
        RECT 111.640 0.000 112.040 0.400 ;
    END
  END S1BEG[2]
  PIN S1BEG[3]
    DIRECTION OUTPUT ;
    USE SIGNAL ;
    ANTENNADIFFAREA 0.708600 ;
    PORT
      LAYER Metal2 ;
        RECT 112.600 0.000 113.000 0.400 ;
    END
  END S1BEG[3]
  PIN S1END[0]
    DIRECTION INPUT ;
    USE SIGNAL ;
    ANTENNAGATEAREA 1.686100 ;
    PORT
      LAYER Metal2 ;
        RECT 109.720 215.060 110.120 215.460 ;
    END
  END S1END[0]
  PIN S1END[1]
    DIRECTION INPUT ;
    USE SIGNAL ;
    ANTENNAGATEAREA 1.705600 ;
    PORT
      LAYER Metal2 ;
        RECT 110.680 215.060 111.080 215.460 ;
    END
  END S1END[1]
  PIN S1END[2]
    DIRECTION INPUT ;
    USE SIGNAL ;
    ANTENNAGATEAREA 1.718600 ;
    PORT
      LAYER Metal2 ;
        RECT 111.640 215.060 112.040 215.460 ;
    END
  END S1END[2]
  PIN S1END[3]
    DIRECTION INPUT ;
    USE SIGNAL ;
    ANTENNAGATEAREA 1.747200 ;
    PORT
      LAYER Metal2 ;
        RECT 112.600 215.060 113.000 215.460 ;
    END
  END S1END[3]
  PIN S2BEG[0]
    DIRECTION OUTPUT ;
    USE SIGNAL ;
    ANTENNADIFFAREA 0.708600 ;
    PORT
      LAYER Metal2 ;
        RECT 113.560 0.000 113.960 0.400 ;
    END
  END S2BEG[0]
  PIN S2BEG[1]
    DIRECTION OUTPUT ;
    USE SIGNAL ;
    ANTENNADIFFAREA 0.708600 ;
    PORT
      LAYER Metal2 ;
        RECT 114.520 0.000 114.920 0.400 ;
    END
  END S2BEG[1]
  PIN S2BEG[2]
    DIRECTION OUTPUT ;
    USE SIGNAL ;
    ANTENNADIFFAREA 0.708600 ;
    PORT
      LAYER Metal2 ;
        RECT 115.480 0.000 115.880 0.400 ;
    END
  END S2BEG[2]
  PIN S2BEG[3]
    DIRECTION OUTPUT ;
    USE SIGNAL ;
    ANTENNADIFFAREA 0.708600 ;
    PORT
      LAYER Metal2 ;
        RECT 116.440 0.000 116.840 0.400 ;
    END
  END S2BEG[3]
  PIN S2BEG[4]
    DIRECTION OUTPUT ;
    USE SIGNAL ;
    ANTENNADIFFAREA 0.708600 ;
    PORT
      LAYER Metal2 ;
        RECT 117.400 0.000 117.800 0.400 ;
    END
  END S2BEG[4]
  PIN S2BEG[5]
    DIRECTION OUTPUT ;
    USE SIGNAL ;
    ANTENNADIFFAREA 0.708600 ;
    PORT
      LAYER Metal2 ;
        RECT 118.360 0.000 118.760 0.400 ;
    END
  END S2BEG[5]
  PIN S2BEG[6]
    DIRECTION OUTPUT ;
    USE SIGNAL ;
    ANTENNADIFFAREA 0.708600 ;
    PORT
      LAYER Metal2 ;
        RECT 119.320 0.000 119.720 0.400 ;
    END
  END S2BEG[6]
  PIN S2BEG[7]
    DIRECTION OUTPUT ;
    USE SIGNAL ;
    ANTENNADIFFAREA 0.708600 ;
    PORT
      LAYER Metal2 ;
        RECT 120.280 0.000 120.680 0.400 ;
    END
  END S2BEG[7]
  PIN S2BEGb[0]
    DIRECTION OUTPUT ;
    USE SIGNAL ;
    ANTENNADIFFAREA 0.708600 ;
    PORT
      LAYER Metal2 ;
        RECT 121.240 0.000 121.640 0.400 ;
    END
  END S2BEGb[0]
  PIN S2BEGb[1]
    DIRECTION OUTPUT ;
    USE SIGNAL ;
    ANTENNADIFFAREA 0.708600 ;
    PORT
      LAYER Metal2 ;
        RECT 122.200 0.000 122.600 0.400 ;
    END
  END S2BEGb[1]
  PIN S2BEGb[2]
    DIRECTION OUTPUT ;
    USE SIGNAL ;
    ANTENNADIFFAREA 0.708600 ;
    PORT
      LAYER Metal2 ;
        RECT 123.160 0.000 123.560 0.400 ;
    END
  END S2BEGb[2]
  PIN S2BEGb[3]
    DIRECTION OUTPUT ;
    USE SIGNAL ;
    ANTENNADIFFAREA 0.708600 ;
    PORT
      LAYER Metal2 ;
        RECT 124.120 0.000 124.520 0.400 ;
    END
  END S2BEGb[3]
  PIN S2BEGb[4]
    DIRECTION OUTPUT ;
    USE SIGNAL ;
    ANTENNADIFFAREA 0.708600 ;
    PORT
      LAYER Metal2 ;
        RECT 125.080 0.000 125.480 0.400 ;
    END
  END S2BEGb[4]
  PIN S2BEGb[5]
    DIRECTION OUTPUT ;
    USE SIGNAL ;
    ANTENNADIFFAREA 0.708600 ;
    PORT
      LAYER Metal2 ;
        RECT 126.040 0.000 126.440 0.400 ;
    END
  END S2BEGb[5]
  PIN S2BEGb[6]
    DIRECTION OUTPUT ;
    USE SIGNAL ;
    ANTENNADIFFAREA 0.708600 ;
    PORT
      LAYER Metal2 ;
        RECT 127.000 0.000 127.400 0.400 ;
    END
  END S2BEGb[6]
  PIN S2BEGb[7]
    DIRECTION OUTPUT ;
    USE SIGNAL ;
    ANTENNADIFFAREA 0.708600 ;
    PORT
      LAYER Metal2 ;
        RECT 127.960 0.000 128.360 0.400 ;
    END
  END S2BEGb[7]
  PIN S2END[0]
    DIRECTION INPUT ;
    USE SIGNAL ;
    ANTENNAGATEAREA 1.760200 ;
    PORT
      LAYER Metal2 ;
        RECT 121.240 215.060 121.640 215.460 ;
    END
  END S2END[0]
  PIN S2END[1]
    DIRECTION INPUT ;
    USE SIGNAL ;
    ANTENNAGATEAREA 1.714700 ;
    PORT
      LAYER Metal2 ;
        RECT 122.200 215.060 122.600 215.460 ;
    END
  END S2END[1]
  PIN S2END[2]
    DIRECTION INPUT ;
    USE SIGNAL ;
    ANTENNAGATEAREA 1.701700 ;
    PORT
      LAYER Metal2 ;
        RECT 123.160 215.060 123.560 215.460 ;
    END
  END S2END[2]
  PIN S2END[3]
    DIRECTION INPUT ;
    USE SIGNAL ;
    ANTENNAGATEAREA 1.501500 ;
    PORT
      LAYER Metal2 ;
        RECT 124.120 215.060 124.520 215.460 ;
    END
  END S2END[3]
  PIN S2END[4]
    DIRECTION INPUT ;
    USE SIGNAL ;
    ANTENNAGATEAREA 1.107600 ;
    PORT
      LAYER Metal2 ;
        RECT 125.080 215.060 125.480 215.460 ;
    END
  END S2END[4]
  PIN S2END[5]
    DIRECTION INPUT ;
    USE SIGNAL ;
    ANTENNAGATEAREA 1.066000 ;
    PORT
      LAYER Metal2 ;
        RECT 126.040 215.060 126.440 215.460 ;
    END
  END S2END[5]
  PIN S2END[6]
    DIRECTION INPUT ;
    USE SIGNAL ;
    ANTENNAGATEAREA 1.079000 ;
    PORT
      LAYER Metal2 ;
        RECT 127.000 215.060 127.400 215.460 ;
    END
  END S2END[6]
  PIN S2END[7]
    DIRECTION INPUT ;
    USE SIGNAL ;
    ANTENNAGATEAREA 1.305200 ;
    PORT
      LAYER Metal2 ;
        RECT 127.960 215.060 128.360 215.460 ;
    END
  END S2END[7]
  PIN S2MID[0]
    DIRECTION INPUT ;
    USE SIGNAL ;
    ANTENNAGATEAREA 0.833300 ;
    PORT
      LAYER Metal2 ;
        RECT 113.560 215.060 113.960 215.460 ;
    END
  END S2MID[0]
  PIN S2MID[1]
    DIRECTION INPUT ;
    USE SIGNAL ;
    ANTENNAGATEAREA 1.014000 ;
    PORT
      LAYER Metal2 ;
        RECT 114.520 215.060 114.920 215.460 ;
    END
  END S2MID[1]
  PIN S2MID[2]
    DIRECTION INPUT ;
    USE SIGNAL ;
    ANTENNAGATEAREA 0.820300 ;
    PORT
      LAYER Metal2 ;
        RECT 115.480 215.060 115.880 215.460 ;
    END
  END S2MID[2]
  PIN S2MID[3]
    DIRECTION INPUT ;
    USE SIGNAL ;
    ANTENNAGATEAREA 1.033500 ;
    PORT
      LAYER Metal2 ;
        RECT 116.440 215.060 116.840 215.460 ;
    END
  END S2MID[3]
  PIN S2MID[4]
    DIRECTION INPUT ;
    USE SIGNAL ;
    ANTENNAGATEAREA 0.820300 ;
    PORT
      LAYER Metal2 ;
        RECT 117.400 215.060 117.800 215.460 ;
    END
  END S2MID[4]
  PIN S2MID[5]
    DIRECTION INPUT ;
    USE SIGNAL ;
    ANTENNAGATEAREA 1.033500 ;
    PORT
      LAYER Metal2 ;
        RECT 118.360 215.060 118.760 215.460 ;
    END
  END S2MID[5]
  PIN S2MID[6]
    DIRECTION INPUT ;
    USE SIGNAL ;
    ANTENNAGATEAREA 0.833300 ;
    PORT
      LAYER Metal2 ;
        RECT 119.320 215.060 119.720 215.460 ;
    END
  END S2MID[6]
  PIN S2MID[7]
    DIRECTION INPUT ;
    USE SIGNAL ;
    ANTENNAGATEAREA 1.046500 ;
    PORT
      LAYER Metal2 ;
        RECT 120.280 215.060 120.680 215.460 ;
    END
  END S2MID[7]
  PIN S4BEG[0]
    DIRECTION OUTPUT ;
    USE SIGNAL ;
    ANTENNADIFFAREA 0.708600 ;
    PORT
      LAYER Metal2 ;
        RECT 128.920 0.000 129.320 0.400 ;
    END
  END S4BEG[0]
  PIN S4BEG[10]
    DIRECTION OUTPUT ;
    USE SIGNAL ;
    ANTENNADIFFAREA 0.708600 ;
    PORT
      LAYER Metal2 ;
        RECT 138.520 0.000 138.920 0.400 ;
    END
  END S4BEG[10]
  PIN S4BEG[11]
    DIRECTION OUTPUT ;
    USE SIGNAL ;
    ANTENNADIFFAREA 0.708600 ;
    PORT
      LAYER Metal2 ;
        RECT 139.480 0.000 139.880 0.400 ;
    END
  END S4BEG[11]
  PIN S4BEG[12]
    DIRECTION OUTPUT ;
    USE SIGNAL ;
    ANTENNADIFFAREA 0.708600 ;
    PORT
      LAYER Metal2 ;
        RECT 140.440 0.000 140.840 0.400 ;
    END
  END S4BEG[12]
  PIN S4BEG[13]
    DIRECTION OUTPUT ;
    USE SIGNAL ;
    ANTENNADIFFAREA 0.708600 ;
    PORT
      LAYER Metal2 ;
        RECT 141.400 0.000 141.800 0.400 ;
    END
  END S4BEG[13]
  PIN S4BEG[14]
    DIRECTION OUTPUT ;
    USE SIGNAL ;
    ANTENNADIFFAREA 0.708600 ;
    PORT
      LAYER Metal2 ;
        RECT 142.360 0.000 142.760 0.400 ;
    END
  END S4BEG[14]
  PIN S4BEG[15]
    DIRECTION OUTPUT ;
    USE SIGNAL ;
    ANTENNADIFFAREA 0.708600 ;
    PORT
      LAYER Metal2 ;
        RECT 143.320 0.000 143.720 0.400 ;
    END
  END S4BEG[15]
  PIN S4BEG[1]
    DIRECTION OUTPUT ;
    USE SIGNAL ;
    ANTENNADIFFAREA 0.708600 ;
    PORT
      LAYER Metal2 ;
        RECT 129.880 0.000 130.280 0.400 ;
    END
  END S4BEG[1]
  PIN S4BEG[2]
    DIRECTION OUTPUT ;
    USE SIGNAL ;
    ANTENNADIFFAREA 0.708600 ;
    PORT
      LAYER Metal2 ;
        RECT 130.840 0.000 131.240 0.400 ;
    END
  END S4BEG[2]
  PIN S4BEG[3]
    DIRECTION OUTPUT ;
    USE SIGNAL ;
    ANTENNADIFFAREA 0.708600 ;
    PORT
      LAYER Metal2 ;
        RECT 131.800 0.000 132.200 0.400 ;
    END
  END S4BEG[3]
  PIN S4BEG[4]
    DIRECTION OUTPUT ;
    USE SIGNAL ;
    ANTENNADIFFAREA 0.708600 ;
    PORT
      LAYER Metal2 ;
        RECT 132.760 0.000 133.160 0.400 ;
    END
  END S4BEG[4]
  PIN S4BEG[5]
    DIRECTION OUTPUT ;
    USE SIGNAL ;
    ANTENNADIFFAREA 0.708600 ;
    PORT
      LAYER Metal2 ;
        RECT 133.720 0.000 134.120 0.400 ;
    END
  END S4BEG[5]
  PIN S4BEG[6]
    DIRECTION OUTPUT ;
    USE SIGNAL ;
    ANTENNADIFFAREA 0.708600 ;
    PORT
      LAYER Metal2 ;
        RECT 134.680 0.000 135.080 0.400 ;
    END
  END S4BEG[6]
  PIN S4BEG[7]
    DIRECTION OUTPUT ;
    USE SIGNAL ;
    ANTENNADIFFAREA 0.708600 ;
    PORT
      LAYER Metal2 ;
        RECT 135.640 0.000 136.040 0.400 ;
    END
  END S4BEG[7]
  PIN S4BEG[8]
    DIRECTION OUTPUT ;
    USE SIGNAL ;
    ANTENNADIFFAREA 0.708600 ;
    PORT
      LAYER Metal2 ;
        RECT 136.600 0.000 137.000 0.400 ;
    END
  END S4BEG[8]
  PIN S4BEG[9]
    DIRECTION OUTPUT ;
    USE SIGNAL ;
    ANTENNADIFFAREA 0.708600 ;
    PORT
      LAYER Metal2 ;
        RECT 137.560 0.000 137.960 0.400 ;
    END
  END S4BEG[9]
  PIN S4END[0]
    DIRECTION INPUT ;
    USE SIGNAL ;
    ANTENNAGATEAREA 1.105000 ;
    PORT
      LAYER Metal2 ;
        RECT 128.920 215.060 129.320 215.460 ;
    END
  END S4END[0]
  PIN S4END[10]
    DIRECTION INPUT ;
    USE SIGNAL ;
    ANTENNAGATEAREA 0.180700 ;
    PORT
      LAYER Metal2 ;
        RECT 138.520 215.060 138.920 215.460 ;
    END
  END S4END[10]
  PIN S4END[11]
    DIRECTION INPUT ;
    USE SIGNAL ;
    ANTENNAGATEAREA 0.180700 ;
    PORT
      LAYER Metal2 ;
        RECT 139.480 215.060 139.880 215.460 ;
    END
  END S4END[11]
  PIN S4END[12]
    DIRECTION INPUT ;
    USE SIGNAL ;
    ANTENNAGATEAREA 0.180700 ;
    PORT
      LAYER Metal2 ;
        RECT 140.440 215.060 140.840 215.460 ;
    END
  END S4END[12]
  PIN S4END[13]
    DIRECTION INPUT ;
    USE SIGNAL ;
    ANTENNAGATEAREA 0.180700 ;
    PORT
      LAYER Metal2 ;
        RECT 141.400 215.060 141.800 215.460 ;
    END
  END S4END[13]
  PIN S4END[14]
    DIRECTION INPUT ;
    USE SIGNAL ;
    ANTENNAGATEAREA 0.180700 ;
    PORT
      LAYER Metal2 ;
        RECT 142.360 215.060 142.760 215.460 ;
    END
  END S4END[14]
  PIN S4END[15]
    DIRECTION INPUT ;
    USE SIGNAL ;
    ANTENNAGATEAREA 0.180700 ;
    PORT
      LAYER Metal2 ;
        RECT 143.320 215.060 143.720 215.460 ;
    END
  END S4END[15]
  PIN S4END[1]
    DIRECTION INPUT ;
    USE SIGNAL ;
    ANTENNAGATEAREA 1.094600 ;
    PORT
      LAYER Metal2 ;
        RECT 129.880 215.060 130.280 215.460 ;
    END
  END S4END[1]
  PIN S4END[2]
    DIRECTION INPUT ;
    USE SIGNAL ;
    ANTENNAGATEAREA 1.079000 ;
    PORT
      LAYER Metal2 ;
        RECT 130.840 215.060 131.240 215.460 ;
    END
  END S4END[2]
  PIN S4END[3]
    DIRECTION INPUT ;
    USE SIGNAL ;
    ANTENNAGATEAREA 1.092000 ;
    PORT
      LAYER Metal2 ;
        RECT 131.800 215.060 132.200 215.460 ;
    END
  END S4END[3]
  PIN S4END[4]
    DIRECTION INPUT ;
    USE SIGNAL ;
    ANTENNAGATEAREA 0.180700 ;
    PORT
      LAYER Metal2 ;
        RECT 132.760 215.060 133.160 215.460 ;
    END
  END S4END[4]
  PIN S4END[5]
    DIRECTION INPUT ;
    USE SIGNAL ;
    ANTENNAGATEAREA 0.789100 ;
    ANTENNADIFFAREA 2.015400 ;
    PORT
      LAYER Metal2 ;
        RECT 133.720 215.060 134.120 215.460 ;
    END
  END S4END[5]
  PIN S4END[6]
    DIRECTION INPUT ;
    USE SIGNAL ;
    ANTENNAGATEAREA 0.789100 ;
    ANTENNADIFFAREA 2.015400 ;
    PORT
      LAYER Metal2 ;
        RECT 134.680 215.060 135.080 215.460 ;
    END
  END S4END[6]
  PIN S4END[7]
    DIRECTION INPUT ;
    USE SIGNAL ;
    ANTENNAGATEAREA 0.180700 ;
    PORT
      LAYER Metal2 ;
        RECT 135.640 215.060 136.040 215.460 ;
    END
  END S4END[7]
  PIN S4END[8]
    DIRECTION INPUT ;
    USE SIGNAL ;
    ANTENNAGATEAREA 0.789100 ;
    ANTENNADIFFAREA 2.015400 ;
    PORT
      LAYER Metal2 ;
        RECT 136.600 215.060 137.000 215.460 ;
    END
  END S4END[8]
  PIN S4END[9]
    DIRECTION INPUT ;
    USE SIGNAL ;
    ANTENNAGATEAREA 0.789100 ;
    ANTENNADIFFAREA 2.015400 ;
    PORT
      LAYER Metal2 ;
        RECT 137.560 215.060 137.960 215.460 ;
    END
  END S4END[9]
  PIN SS4BEG[0]
    DIRECTION OUTPUT ;
    USE SIGNAL ;
    ANTENNADIFFAREA 0.708600 ;
    PORT
      LAYER Metal2 ;
        RECT 144.280 0.000 144.680 0.400 ;
    END
  END SS4BEG[0]
  PIN SS4BEG[10]
    DIRECTION OUTPUT ;
    USE SIGNAL ;
    ANTENNADIFFAREA 0.708600 ;
    PORT
      LAYER Metal2 ;
        RECT 153.880 0.000 154.280 0.400 ;
    END
  END SS4BEG[10]
  PIN SS4BEG[11]
    DIRECTION OUTPUT ;
    USE SIGNAL ;
    ANTENNADIFFAREA 0.708600 ;
    PORT
      LAYER Metal2 ;
        RECT 154.840 0.000 155.240 0.400 ;
    END
  END SS4BEG[11]
  PIN SS4BEG[12]
    DIRECTION OUTPUT ;
    USE SIGNAL ;
    ANTENNADIFFAREA 0.708600 ;
    PORT
      LAYER Metal2 ;
        RECT 155.800 0.000 156.200 0.400 ;
    END
  END SS4BEG[12]
  PIN SS4BEG[13]
    DIRECTION OUTPUT ;
    USE SIGNAL ;
    ANTENNADIFFAREA 0.708600 ;
    PORT
      LAYER Metal2 ;
        RECT 156.760 0.000 157.160 0.400 ;
    END
  END SS4BEG[13]
  PIN SS4BEG[14]
    DIRECTION OUTPUT ;
    USE SIGNAL ;
    ANTENNADIFFAREA 0.708600 ;
    PORT
      LAYER Metal2 ;
        RECT 157.720 0.000 158.120 0.400 ;
    END
  END SS4BEG[14]
  PIN SS4BEG[15]
    DIRECTION OUTPUT ;
    USE SIGNAL ;
    ANTENNADIFFAREA 0.708600 ;
    PORT
      LAYER Metal2 ;
        RECT 158.680 0.000 159.080 0.400 ;
    END
  END SS4BEG[15]
  PIN SS4BEG[1]
    DIRECTION OUTPUT ;
    USE SIGNAL ;
    ANTENNADIFFAREA 0.708600 ;
    PORT
      LAYER Metal2 ;
        RECT 145.240 0.000 145.640 0.400 ;
    END
  END SS4BEG[1]
  PIN SS4BEG[2]
    DIRECTION OUTPUT ;
    USE SIGNAL ;
    ANTENNADIFFAREA 0.708600 ;
    PORT
      LAYER Metal2 ;
        RECT 146.200 0.000 146.600 0.400 ;
    END
  END SS4BEG[2]
  PIN SS4BEG[3]
    DIRECTION OUTPUT ;
    USE SIGNAL ;
    ANTENNADIFFAREA 0.708600 ;
    PORT
      LAYER Metal2 ;
        RECT 147.160 0.000 147.560 0.400 ;
    END
  END SS4BEG[3]
  PIN SS4BEG[4]
    DIRECTION OUTPUT ;
    USE SIGNAL ;
    ANTENNADIFFAREA 0.708600 ;
    PORT
      LAYER Metal2 ;
        RECT 148.120 0.000 148.520 0.400 ;
    END
  END SS4BEG[4]
  PIN SS4BEG[5]
    DIRECTION OUTPUT ;
    USE SIGNAL ;
    ANTENNADIFFAREA 0.708600 ;
    PORT
      LAYER Metal2 ;
        RECT 149.080 0.000 149.480 0.400 ;
    END
  END SS4BEG[5]
  PIN SS4BEG[6]
    DIRECTION OUTPUT ;
    USE SIGNAL ;
    ANTENNADIFFAREA 0.708600 ;
    PORT
      LAYER Metal2 ;
        RECT 150.040 0.000 150.440 0.400 ;
    END
  END SS4BEG[6]
  PIN SS4BEG[7]
    DIRECTION OUTPUT ;
    USE SIGNAL ;
    ANTENNADIFFAREA 0.708600 ;
    PORT
      LAYER Metal2 ;
        RECT 151.000 0.000 151.400 0.400 ;
    END
  END SS4BEG[7]
  PIN SS4BEG[8]
    DIRECTION OUTPUT ;
    USE SIGNAL ;
    ANTENNADIFFAREA 0.708600 ;
    PORT
      LAYER Metal2 ;
        RECT 151.960 0.000 152.360 0.400 ;
    END
  END SS4BEG[8]
  PIN SS4BEG[9]
    DIRECTION OUTPUT ;
    USE SIGNAL ;
    ANTENNADIFFAREA 0.708600 ;
    PORT
      LAYER Metal2 ;
        RECT 152.920 0.000 153.320 0.400 ;
    END
  END SS4BEG[9]
  PIN SS4END[0]
    DIRECTION INPUT ;
    USE SIGNAL ;
    ANTENNAGATEAREA 1.046500 ;
    PORT
      LAYER Metal2 ;
        RECT 144.280 215.060 144.680 215.460 ;
    END
  END SS4END[0]
  PIN SS4END[10]
    DIRECTION INPUT ;
    USE SIGNAL ;
    ANTENNAGATEAREA 0.180700 ;
    PORT
      LAYER Metal2 ;
        RECT 153.880 215.060 154.280 215.460 ;
    END
  END SS4END[10]
  PIN SS4END[11]
    DIRECTION INPUT ;
    USE SIGNAL ;
    ANTENNAGATEAREA 0.180700 ;
    PORT
      LAYER Metal2 ;
        RECT 154.840 215.060 155.240 215.460 ;
    END
  END SS4END[11]
  PIN SS4END[12]
    DIRECTION INPUT ;
    USE SIGNAL ;
    ANTENNAGATEAREA 0.180700 ;
    PORT
      LAYER Metal2 ;
        RECT 155.800 215.060 156.200 215.460 ;
    END
  END SS4END[12]
  PIN SS4END[13]
    DIRECTION INPUT ;
    USE SIGNAL ;
    ANTENNAGATEAREA 0.180700 ;
    PORT
      LAYER Metal2 ;
        RECT 156.760 215.060 157.160 215.460 ;
    END
  END SS4END[13]
  PIN SS4END[14]
    DIRECTION INPUT ;
    USE SIGNAL ;
    ANTENNAGATEAREA 0.180700 ;
    PORT
      LAYER Metal2 ;
        RECT 157.720 215.060 158.120 215.460 ;
    END
  END SS4END[14]
  PIN SS4END[15]
    DIRECTION INPUT ;
    USE SIGNAL ;
    ANTENNAGATEAREA 0.180700 ;
    PORT
      LAYER Metal2 ;
        RECT 158.680 215.060 159.080 215.460 ;
    END
  END SS4END[15]
  PIN SS4END[1]
    DIRECTION INPUT ;
    USE SIGNAL ;
    ANTENNAGATEAREA 1.046500 ;
    PORT
      LAYER Metal2 ;
        RECT 145.240 215.060 145.640 215.460 ;
    END
  END SS4END[1]
  PIN SS4END[2]
    DIRECTION INPUT ;
    USE SIGNAL ;
    ANTENNAGATEAREA 1.107600 ;
    PORT
      LAYER Metal2 ;
        RECT 146.200 215.060 146.600 215.460 ;
    END
  END SS4END[2]
  PIN SS4END[3]
    DIRECTION INPUT ;
    USE SIGNAL ;
    ANTENNAGATEAREA 1.094600 ;
    PORT
      LAYER Metal2 ;
        RECT 147.160 215.060 147.560 215.460 ;
    END
  END SS4END[3]
  PIN SS4END[4]
    DIRECTION INPUT ;
    USE SIGNAL ;
    ANTENNAGATEAREA 0.180700 ;
    PORT
      LAYER Metal2 ;
        RECT 148.120 215.060 148.520 215.460 ;
    END
  END SS4END[4]
  PIN SS4END[5]
    DIRECTION INPUT ;
    USE SIGNAL ;
    ANTENNAGATEAREA 0.180700 ;
    PORT
      LAYER Metal2 ;
        RECT 149.080 215.060 149.480 215.460 ;
    END
  END SS4END[5]
  PIN SS4END[6]
    DIRECTION INPUT ;
    USE SIGNAL ;
    ANTENNAGATEAREA 0.180700 ;
    PORT
      LAYER Metal2 ;
        RECT 150.040 215.060 150.440 215.460 ;
    END
  END SS4END[6]
  PIN SS4END[7]
    DIRECTION INPUT ;
    USE SIGNAL ;
    ANTENNAGATEAREA 0.180700 ;
    PORT
      LAYER Metal2 ;
        RECT 151.000 215.060 151.400 215.460 ;
    END
  END SS4END[7]
  PIN SS4END[8]
    DIRECTION INPUT ;
    USE SIGNAL ;
    ANTENNAGATEAREA 0.180700 ;
    PORT
      LAYER Metal2 ;
        RECT 151.960 215.060 152.360 215.460 ;
    END
  END SS4END[8]
  PIN SS4END[9]
    DIRECTION INPUT ;
    USE SIGNAL ;
    ANTENNAGATEAREA 0.180700 ;
    PORT
      LAYER Metal2 ;
        RECT 152.920 215.060 153.320 215.460 ;
    END
  END SS4END[9]
  PIN UserCLK
    DIRECTION INPUT ;
    USE SIGNAL ;
    ANTENNAGATEAREA 1.450800 ;
    PORT
      LAYER Metal2 ;
        RECT 159.640 0.000 160.040 0.400 ;
    END
  END UserCLK
  PIN UserCLKo
    DIRECTION OUTPUT ;
    USE SIGNAL ;
    ANTENNADIFFAREA 0.708600 ;
    PORT
      LAYER Metal2 ;
        RECT 159.640 215.060 160.040 215.460 ;
    END
  END UserCLKo
  PIN VGND
    DIRECTION INOUT ;
    USE GROUND ;
    PORT
      LAYER TopMetal1 ;
        RECT 21.580 0.000 23.780 215.460 ;
    END
    PORT
      LAYER TopMetal1 ;
        RECT 97.180 0.000 99.380 215.460 ;
    END
    PORT
      LAYER TopMetal1 ;
        RECT 172.780 0.000 174.980 215.460 ;
    END
  END VGND
  PIN VPWR
    DIRECTION INOUT ;
    USE POWER ;
    PORT
      LAYER TopMetal1 ;
        RECT 15.380 0.000 17.580 215.460 ;
    END
    PORT
      LAYER TopMetal1 ;
        RECT 90.980 0.000 93.180 215.460 ;
    END
    PORT
      LAYER TopMetal1 ;
        RECT 166.580 0.000 168.780 215.460 ;
    END
  END VPWR
  PIN W1BEG[0]
    DIRECTION OUTPUT ;
    USE SIGNAL ;
    ANTENNADIFFAREA 0.708600 ;
    PORT
      LAYER Metal3 ;
        RECT 0.000 0.220 0.400 0.620 ;
    END
  END W1BEG[0]
  PIN W1BEG[1]
    DIRECTION OUTPUT ;
    USE SIGNAL ;
    ANTENNADIFFAREA 0.708600 ;
    PORT
      LAYER Metal3 ;
        RECT 0.000 1.900 0.400 2.300 ;
    END
  END W1BEG[1]
  PIN W1BEG[2]
    DIRECTION OUTPUT ;
    USE SIGNAL ;
    ANTENNADIFFAREA 0.708600 ;
    PORT
      LAYER Metal3 ;
        RECT 0.000 3.580 0.400 3.980 ;
    END
  END W1BEG[2]
  PIN W1BEG[3]
    DIRECTION OUTPUT ;
    USE SIGNAL ;
    ANTENNADIFFAREA 0.708600 ;
    PORT
      LAYER Metal3 ;
        RECT 0.000 5.260 0.400 5.660 ;
    END
  END W1BEG[3]
  PIN W1END[0]
    DIRECTION INPUT ;
    USE SIGNAL ;
    ANTENNAGATEAREA 1.957800 ;
    PORT
      LAYER Metal3 ;
        RECT 238.640 0.220 239.040 0.620 ;
    END
  END W1END[0]
  PIN W1END[1]
    DIRECTION INPUT ;
    USE SIGNAL ;
    ANTENNAGATEAREA 1.957800 ;
    PORT
      LAYER Metal3 ;
        RECT 238.640 1.900 239.040 2.300 ;
    END
  END W1END[1]
  PIN W1END[2]
    DIRECTION INPUT ;
    USE SIGNAL ;
    ANTENNAGATEAREA 2.280200 ;
    PORT
      LAYER Metal3 ;
        RECT 238.640 3.580 239.040 3.980 ;
    END
  END W1END[2]
  PIN W1END[3]
    DIRECTION INPUT ;
    USE SIGNAL ;
    ANTENNAGATEAREA 2.333500 ;
    PORT
      LAYER Metal3 ;
        RECT 238.640 5.260 239.040 5.660 ;
    END
  END W1END[3]
  PIN W2BEG[0]
    DIRECTION OUTPUT ;
    USE SIGNAL ;
    ANTENNADIFFAREA 0.708600 ;
    PORT
      LAYER Metal3 ;
        RECT 0.000 6.940 0.400 7.340 ;
    END
  END W2BEG[0]
  PIN W2BEG[1]
    DIRECTION OUTPUT ;
    USE SIGNAL ;
    ANTENNADIFFAREA 0.708600 ;
    PORT
      LAYER Metal3 ;
        RECT 0.000 8.620 0.400 9.020 ;
    END
  END W2BEG[1]
  PIN W2BEG[2]
    DIRECTION OUTPUT ;
    USE SIGNAL ;
    ANTENNADIFFAREA 0.708600 ;
    PORT
      LAYER Metal3 ;
        RECT 0.000 10.300 0.400 10.700 ;
    END
  END W2BEG[2]
  PIN W2BEG[3]
    DIRECTION OUTPUT ;
    USE SIGNAL ;
    ANTENNADIFFAREA 0.708600 ;
    PORT
      LAYER Metal3 ;
        RECT 0.000 11.980 0.400 12.380 ;
    END
  END W2BEG[3]
  PIN W2BEG[4]
    DIRECTION OUTPUT ;
    USE SIGNAL ;
    ANTENNADIFFAREA 0.708600 ;
    PORT
      LAYER Metal3 ;
        RECT 0.000 13.660 0.400 14.060 ;
    END
  END W2BEG[4]
  PIN W2BEG[5]
    DIRECTION OUTPUT ;
    USE SIGNAL ;
    ANTENNADIFFAREA 0.708600 ;
    PORT
      LAYER Metal3 ;
        RECT 0.000 15.340 0.400 15.740 ;
    END
  END W2BEG[5]
  PIN W2BEG[6]
    DIRECTION OUTPUT ;
    USE SIGNAL ;
    ANTENNADIFFAREA 0.708600 ;
    PORT
      LAYER Metal3 ;
        RECT 0.000 17.020 0.400 17.420 ;
    END
  END W2BEG[6]
  PIN W2BEG[7]
    DIRECTION OUTPUT ;
    USE SIGNAL ;
    ANTENNADIFFAREA 0.708600 ;
    PORT
      LAYER Metal3 ;
        RECT 0.000 18.700 0.400 19.100 ;
    END
  END W2BEG[7]
  PIN W2BEGb[0]
    DIRECTION OUTPUT ;
    USE SIGNAL ;
    ANTENNADIFFAREA 0.708600 ;
    PORT
      LAYER Metal3 ;
        RECT 0.000 20.380 0.400 20.780 ;
    END
  END W2BEGb[0]
  PIN W2BEGb[1]
    DIRECTION OUTPUT ;
    USE SIGNAL ;
    ANTENNADIFFAREA 0.708600 ;
    PORT
      LAYER Metal3 ;
        RECT 0.000 22.060 0.400 22.460 ;
    END
  END W2BEGb[1]
  PIN W2BEGb[2]
    DIRECTION OUTPUT ;
    USE SIGNAL ;
    ANTENNADIFFAREA 0.708600 ;
    PORT
      LAYER Metal3 ;
        RECT 0.000 23.740 0.400 24.140 ;
    END
  END W2BEGb[2]
  PIN W2BEGb[3]
    DIRECTION OUTPUT ;
    USE SIGNAL ;
    ANTENNADIFFAREA 0.708600 ;
    PORT
      LAYER Metal3 ;
        RECT 0.000 25.420 0.400 25.820 ;
    END
  END W2BEGb[3]
  PIN W2BEGb[4]
    DIRECTION OUTPUT ;
    USE SIGNAL ;
    ANTENNADIFFAREA 0.708600 ;
    PORT
      LAYER Metal3 ;
        RECT 0.000 27.100 0.400 27.500 ;
    END
  END W2BEGb[4]
  PIN W2BEGb[5]
    DIRECTION OUTPUT ;
    USE SIGNAL ;
    ANTENNADIFFAREA 0.708600 ;
    PORT
      LAYER Metal3 ;
        RECT 0.000 28.780 0.400 29.180 ;
    END
  END W2BEGb[5]
  PIN W2BEGb[6]
    DIRECTION OUTPUT ;
    USE SIGNAL ;
    ANTENNADIFFAREA 0.708600 ;
    PORT
      LAYER Metal3 ;
        RECT 0.000 30.460 0.400 30.860 ;
    END
  END W2BEGb[6]
  PIN W2BEGb[7]
    DIRECTION OUTPUT ;
    USE SIGNAL ;
    ANTENNADIFFAREA 0.708600 ;
    PORT
      LAYER Metal3 ;
        RECT 0.000 32.140 0.400 32.540 ;
    END
  END W2BEGb[7]
  PIN W2END[0]
    DIRECTION INPUT ;
    USE SIGNAL ;
    ANTENNAGATEAREA 0.426400 ;
    PORT
      LAYER Metal3 ;
        RECT 238.640 20.380 239.040 20.780 ;
    END
  END W2END[0]
  PIN W2END[1]
    DIRECTION INPUT ;
    USE SIGNAL ;
    ANTENNAGATEAREA 1.305200 ;
    PORT
      LAYER Metal3 ;
        RECT 238.640 22.060 239.040 22.460 ;
    END
  END W2END[1]
  PIN W2END[2]
    DIRECTION INPUT ;
    USE SIGNAL ;
    ANTENNAGATEAREA 1.373600 ;
    PORT
      LAYER Metal3 ;
        RECT 238.640 23.740 239.040 24.140 ;
    END
  END W2END[2]
  PIN W2END[3]
    DIRECTION INPUT ;
    USE SIGNAL ;
    ANTENNAGATEAREA 4.968600 ;
    ANTENNADIFFAREA 12.092400 ;
    PORT
      LAYER Metal3 ;
        RECT 238.640 25.420 239.040 25.820 ;
    END
  END W2END[3]
  PIN W2END[4]
    DIRECTION INPUT ;
    USE SIGNAL ;
    ANTENNAGATEAREA 5.777200 ;
    ANTENNADIFFAREA 14.107800 ;
    PORT
      LAYER Metal3 ;
        RECT 238.640 27.100 239.040 27.500 ;
    END
  END W2END[4]
  PIN W2END[5]
    DIRECTION INPUT ;
    USE SIGNAL ;
    ANTENNAGATEAREA 0.426400 ;
    PORT
      LAYER Metal3 ;
        RECT 238.640 28.780 239.040 29.180 ;
    END
  END W2END[5]
  PIN W2END[6]
    DIRECTION INPUT ;
    USE SIGNAL ;
    ANTENNAGATEAREA 0.426400 ;
    PORT
      LAYER Metal3 ;
        RECT 238.640 30.460 239.040 30.860 ;
    END
  END W2END[6]
  PIN W2END[7]
    DIRECTION INPUT ;
    USE SIGNAL ;
    ANTENNAGATEAREA 0.639600 ;
    PORT
      LAYER Metal3 ;
        RECT 238.640 32.140 239.040 32.540 ;
    END
  END W2END[7]
  PIN W2MID[0]
    DIRECTION INPUT ;
    USE SIGNAL ;
    ANTENNAGATEAREA 0.787800 ;
    PORT
      LAYER Metal3 ;
        RECT 238.640 6.940 239.040 7.340 ;
    END
  END W2MID[0]
  PIN W2MID[1]
    DIRECTION INPUT ;
    USE SIGNAL ;
    ANTENNAGATEAREA 1.075100 ;
    PORT
      LAYER Metal3 ;
        RECT 238.640 8.620 239.040 9.020 ;
    END
  END W2MID[1]
  PIN W2MID[2]
    DIRECTION INPUT ;
    USE SIGNAL ;
    ANTENNAGATEAREA 0.820300 ;
    PORT
      LAYER Metal3 ;
        RECT 238.640 10.300 239.040 10.700 ;
    END
  END W2MID[2]
  PIN W2MID[3]
    DIRECTION INPUT ;
    USE SIGNAL ;
    ANTENNAGATEAREA 1.033500 ;
    PORT
      LAYER Metal3 ;
        RECT 238.640 11.980 239.040 12.380 ;
    END
  END W2MID[3]
  PIN W2MID[4]
    DIRECTION INPUT ;
    USE SIGNAL ;
    ANTENNAGATEAREA 0.820300 ;
    PORT
      LAYER Metal3 ;
        RECT 238.640 13.660 239.040 14.060 ;
    END
  END W2MID[4]
  PIN W2MID[5]
    DIRECTION INPUT ;
    USE SIGNAL ;
    ANTENNAGATEAREA 1.033500 ;
    PORT
      LAYER Metal3 ;
        RECT 238.640 15.340 239.040 15.740 ;
    END
  END W2MID[5]
  PIN W2MID[6]
    DIRECTION INPUT ;
    USE SIGNAL ;
    ANTENNAGATEAREA 0.820300 ;
    PORT
      LAYER Metal3 ;
        RECT 238.640 17.020 239.040 17.420 ;
    END
  END W2MID[6]
  PIN W2MID[7]
    DIRECTION INPUT ;
    USE SIGNAL ;
    ANTENNAGATEAREA 1.046500 ;
    PORT
      LAYER Metal3 ;
        RECT 238.640 18.700 239.040 19.100 ;
    END
  END W2MID[7]
  PIN W6BEG[0]
    DIRECTION OUTPUT ;
    USE SIGNAL ;
    ANTENNADIFFAREA 0.708600 ;
    PORT
      LAYER Metal3 ;
        RECT 0.000 60.700 0.400 61.100 ;
    END
  END W6BEG[0]
  PIN W6BEG[10]
    DIRECTION OUTPUT ;
    USE SIGNAL ;
    ANTENNADIFFAREA 0.708600 ;
    PORT
      LAYER Metal3 ;
        RECT 0.000 77.500 0.400 77.900 ;
    END
  END W6BEG[10]
  PIN W6BEG[11]
    DIRECTION OUTPUT ;
    USE SIGNAL ;
    ANTENNADIFFAREA 0.708600 ;
    PORT
      LAYER Metal3 ;
        RECT 0.000 79.180 0.400 79.580 ;
    END
  END W6BEG[11]
  PIN W6BEG[1]
    DIRECTION OUTPUT ;
    USE SIGNAL ;
    ANTENNADIFFAREA 0.708600 ;
    PORT
      LAYER Metal3 ;
        RECT 0.000 62.380 0.400 62.780 ;
    END
  END W6BEG[1]
  PIN W6BEG[2]
    DIRECTION OUTPUT ;
    USE SIGNAL ;
    ANTENNADIFFAREA 0.708600 ;
    PORT
      LAYER Metal3 ;
        RECT 0.000 64.060 0.400 64.460 ;
    END
  END W6BEG[2]
  PIN W6BEG[3]
    DIRECTION OUTPUT ;
    USE SIGNAL ;
    ANTENNADIFFAREA 0.708600 ;
    PORT
      LAYER Metal3 ;
        RECT 0.000 65.740 0.400 66.140 ;
    END
  END W6BEG[3]
  PIN W6BEG[4]
    DIRECTION OUTPUT ;
    USE SIGNAL ;
    ANTENNADIFFAREA 0.708600 ;
    PORT
      LAYER Metal3 ;
        RECT 0.000 67.420 0.400 67.820 ;
    END
  END W6BEG[4]
  PIN W6BEG[5]
    DIRECTION OUTPUT ;
    USE SIGNAL ;
    ANTENNADIFFAREA 0.708600 ;
    PORT
      LAYER Metal3 ;
        RECT 0.000 69.100 0.400 69.500 ;
    END
  END W6BEG[5]
  PIN W6BEG[6]
    DIRECTION OUTPUT ;
    USE SIGNAL ;
    ANTENNADIFFAREA 0.708600 ;
    PORT
      LAYER Metal3 ;
        RECT 0.000 70.780 0.400 71.180 ;
    END
  END W6BEG[6]
  PIN W6BEG[7]
    DIRECTION OUTPUT ;
    USE SIGNAL ;
    ANTENNADIFFAREA 0.708600 ;
    PORT
      LAYER Metal3 ;
        RECT 0.000 72.460 0.400 72.860 ;
    END
  END W6BEG[7]
  PIN W6BEG[8]
    DIRECTION OUTPUT ;
    USE SIGNAL ;
    ANTENNADIFFAREA 0.708600 ;
    PORT
      LAYER Metal3 ;
        RECT 0.000 74.140 0.400 74.540 ;
    END
  END W6BEG[8]
  PIN W6BEG[9]
    DIRECTION OUTPUT ;
    USE SIGNAL ;
    ANTENNADIFFAREA 0.708600 ;
    PORT
      LAYER Metal3 ;
        RECT 0.000 75.820 0.400 76.220 ;
    END
  END W6BEG[9]
  PIN W6END[0]
    DIRECTION INPUT ;
    USE SIGNAL ;
    ANTENNAGATEAREA 2.150200 ;
    PORT
      LAYER Metal3 ;
        RECT 238.640 60.700 239.040 61.100 ;
    END
  END W6END[0]
  PIN W6END[10]
    DIRECTION INPUT ;
    USE SIGNAL ;
    ANTENNAGATEAREA 0.789100 ;
    ANTENNADIFFAREA 2.015400 ;
    PORT
      LAYER Metal3 ;
        RECT 238.640 77.500 239.040 77.900 ;
    END
  END W6END[10]
  PIN W6END[11]
    DIRECTION INPUT ;
    USE SIGNAL ;
    ANTENNAGATEAREA 0.789100 ;
    ANTENNADIFFAREA 2.015400 ;
    PORT
      LAYER Metal3 ;
        RECT 238.640 79.180 239.040 79.580 ;
    END
  END W6END[11]
  PIN W6END[1]
    DIRECTION INPUT ;
    USE SIGNAL ;
    ANTENNAGATEAREA 2.215200 ;
    PORT
      LAYER Metal3 ;
        RECT 238.640 62.380 239.040 62.780 ;
    END
  END W6END[1]
  PIN W6END[2]
    DIRECTION INPUT ;
    USE SIGNAL ;
    ANTENNAGATEAREA 0.789100 ;
    ANTENNADIFFAREA 2.015400 ;
    PORT
      LAYER Metal3 ;
        RECT 238.640 64.060 239.040 64.460 ;
    END
  END W6END[2]
  PIN W6END[3]
    DIRECTION INPUT ;
    USE SIGNAL ;
    ANTENNAGATEAREA 0.789100 ;
    ANTENNADIFFAREA 2.015400 ;
    PORT
      LAYER Metal3 ;
        RECT 238.640 65.740 239.040 66.140 ;
    END
  END W6END[3]
  PIN W6END[4]
    DIRECTION INPUT ;
    USE SIGNAL ;
    ANTENNAGATEAREA 0.789100 ;
    ANTENNADIFFAREA 2.015400 ;
    PORT
      LAYER Metal3 ;
        RECT 238.640 67.420 239.040 67.820 ;
    END
  END W6END[4]
  PIN W6END[5]
    DIRECTION INPUT ;
    USE SIGNAL ;
    ANTENNAGATEAREA 0.789100 ;
    ANTENNADIFFAREA 2.015400 ;
    PORT
      LAYER Metal3 ;
        RECT 238.640 69.100 239.040 69.500 ;
    END
  END W6END[5]
  PIN W6END[6]
    DIRECTION INPUT ;
    USE SIGNAL ;
    ANTENNAGATEAREA 0.789100 ;
    ANTENNADIFFAREA 2.015400 ;
    PORT
      LAYER Metal3 ;
        RECT 238.640 70.780 239.040 71.180 ;
    END
  END W6END[6]
  PIN W6END[7]
    DIRECTION INPUT ;
    USE SIGNAL ;
    ANTENNAGATEAREA 0.789100 ;
    ANTENNADIFFAREA 2.015400 ;
    PORT
      LAYER Metal3 ;
        RECT 238.640 72.460 239.040 72.860 ;
    END
  END W6END[7]
  PIN W6END[8]
    DIRECTION INPUT ;
    USE SIGNAL ;
    ANTENNAGATEAREA 0.789100 ;
    ANTENNADIFFAREA 2.015400 ;
    PORT
      LAYER Metal3 ;
        RECT 238.640 74.140 239.040 74.540 ;
    END
  END W6END[8]
  PIN W6END[9]
    DIRECTION INPUT ;
    USE SIGNAL ;
    ANTENNAGATEAREA 0.789100 ;
    ANTENNADIFFAREA 2.015400 ;
    PORT
      LAYER Metal3 ;
        RECT 238.640 75.820 239.040 76.220 ;
    END
  END W6END[9]
  PIN WW4BEG[0]
    DIRECTION OUTPUT ;
    USE SIGNAL ;
    ANTENNADIFFAREA 0.708600 ;
    PORT
      LAYER Metal3 ;
        RECT 0.000 33.820 0.400 34.220 ;
    END
  END WW4BEG[0]
  PIN WW4BEG[10]
    DIRECTION OUTPUT ;
    USE SIGNAL ;
    ANTENNADIFFAREA 0.708600 ;
    PORT
      LAYER Metal3 ;
        RECT 0.000 50.620 0.400 51.020 ;
    END
  END WW4BEG[10]
  PIN WW4BEG[11]
    DIRECTION OUTPUT ;
    USE SIGNAL ;
    ANTENNADIFFAREA 0.708600 ;
    PORT
      LAYER Metal3 ;
        RECT 0.000 52.300 0.400 52.700 ;
    END
  END WW4BEG[11]
  PIN WW4BEG[12]
    DIRECTION OUTPUT ;
    USE SIGNAL ;
    ANTENNADIFFAREA 0.708600 ;
    PORT
      LAYER Metal3 ;
        RECT 0.000 53.980 0.400 54.380 ;
    END
  END WW4BEG[12]
  PIN WW4BEG[13]
    DIRECTION OUTPUT ;
    USE SIGNAL ;
    ANTENNADIFFAREA 0.708600 ;
    PORT
      LAYER Metal3 ;
        RECT 0.000 55.660 0.400 56.060 ;
    END
  END WW4BEG[13]
  PIN WW4BEG[14]
    DIRECTION OUTPUT ;
    USE SIGNAL ;
    ANTENNADIFFAREA 0.708600 ;
    PORT
      LAYER Metal3 ;
        RECT 0.000 57.340 0.400 57.740 ;
    END
  END WW4BEG[14]
  PIN WW4BEG[15]
    DIRECTION OUTPUT ;
    USE SIGNAL ;
    ANTENNADIFFAREA 0.708600 ;
    PORT
      LAYER Metal3 ;
        RECT 0.000 59.020 0.400 59.420 ;
    END
  END WW4BEG[15]
  PIN WW4BEG[1]
    DIRECTION OUTPUT ;
    USE SIGNAL ;
    ANTENNADIFFAREA 0.708600 ;
    PORT
      LAYER Metal3 ;
        RECT 0.000 35.500 0.400 35.900 ;
    END
  END WW4BEG[1]
  PIN WW4BEG[2]
    DIRECTION OUTPUT ;
    USE SIGNAL ;
    ANTENNADIFFAREA 0.708600 ;
    PORT
      LAYER Metal3 ;
        RECT 0.000 37.180 0.400 37.580 ;
    END
  END WW4BEG[2]
  PIN WW4BEG[3]
    DIRECTION OUTPUT ;
    USE SIGNAL ;
    ANTENNADIFFAREA 0.708600 ;
    PORT
      LAYER Metal3 ;
        RECT 0.000 38.860 0.400 39.260 ;
    END
  END WW4BEG[3]
  PIN WW4BEG[4]
    DIRECTION OUTPUT ;
    USE SIGNAL ;
    ANTENNADIFFAREA 0.708600 ;
    PORT
      LAYER Metal3 ;
        RECT 0.000 40.540 0.400 40.940 ;
    END
  END WW4BEG[4]
  PIN WW4BEG[5]
    DIRECTION OUTPUT ;
    USE SIGNAL ;
    ANTENNADIFFAREA 0.708600 ;
    PORT
      LAYER Metal3 ;
        RECT 0.000 42.220 0.400 42.620 ;
    END
  END WW4BEG[5]
  PIN WW4BEG[6]
    DIRECTION OUTPUT ;
    USE SIGNAL ;
    ANTENNADIFFAREA 0.708600 ;
    PORT
      LAYER Metal3 ;
        RECT 0.000 43.900 0.400 44.300 ;
    END
  END WW4BEG[6]
  PIN WW4BEG[7]
    DIRECTION OUTPUT ;
    USE SIGNAL ;
    ANTENNADIFFAREA 0.708600 ;
    PORT
      LAYER Metal3 ;
        RECT 0.000 45.580 0.400 45.980 ;
    END
  END WW4BEG[7]
  PIN WW4BEG[8]
    DIRECTION OUTPUT ;
    USE SIGNAL ;
    ANTENNADIFFAREA 0.708600 ;
    PORT
      LAYER Metal3 ;
        RECT 0.000 47.260 0.400 47.660 ;
    END
  END WW4BEG[8]
  PIN WW4BEG[9]
    DIRECTION OUTPUT ;
    USE SIGNAL ;
    ANTENNADIFFAREA 0.708600 ;
    PORT
      LAYER Metal3 ;
        RECT 0.000 48.940 0.400 49.340 ;
    END
  END WW4BEG[9]
  PIN WW4END[0]
    DIRECTION INPUT ;
    USE SIGNAL ;
    ANTENNAGATEAREA 0.833300 ;
    PORT
      LAYER Metal3 ;
        RECT 238.640 33.820 239.040 34.220 ;
    END
  END WW4END[0]
  PIN WW4END[10]
    DIRECTION INPUT ;
    USE SIGNAL ;
    ANTENNAGATEAREA 0.789100 ;
    ANTENNADIFFAREA 2.015400 ;
    PORT
      LAYER Metal3 ;
        RECT 238.640 50.620 239.040 51.020 ;
    END
  END WW4END[10]
  PIN WW4END[11]
    DIRECTION INPUT ;
    USE SIGNAL ;
    ANTENNAGATEAREA 0.789100 ;
    ANTENNADIFFAREA 2.015400 ;
    PORT
      LAYER Metal3 ;
        RECT 238.640 52.300 239.040 52.700 ;
    END
  END WW4END[11]
  PIN WW4END[12]
    DIRECTION INPUT ;
    USE SIGNAL ;
    ANTENNAGATEAREA 0.789100 ;
    ANTENNADIFFAREA 2.015400 ;
    PORT
      LAYER Metal3 ;
        RECT 238.640 53.980 239.040 54.380 ;
    END
  END WW4END[12]
  PIN WW4END[13]
    DIRECTION INPUT ;
    USE SIGNAL ;
    ANTENNAGATEAREA 0.789100 ;
    ANTENNADIFFAREA 2.015400 ;
    PORT
      LAYER Metal3 ;
        RECT 238.640 55.660 239.040 56.060 ;
    END
  END WW4END[13]
  PIN WW4END[14]
    DIRECTION INPUT ;
    USE SIGNAL ;
    ANTENNAGATEAREA 0.789100 ;
    ANTENNADIFFAREA 2.015400 ;
    PORT
      LAYER Metal3 ;
        RECT 238.640 57.340 239.040 57.740 ;
    END
  END WW4END[14]
  PIN WW4END[15]
    DIRECTION INPUT ;
    USE SIGNAL ;
    ANTENNAGATEAREA 0.789100 ;
    ANTENNADIFFAREA 2.015400 ;
    PORT
      LAYER Metal3 ;
        RECT 238.640 59.020 239.040 59.420 ;
    END
  END WW4END[15]
  PIN WW4END[1]
    DIRECTION INPUT ;
    USE SIGNAL ;
    ANTENNAGATEAREA 3.315000 ;
    ANTENNADIFFAREA 8.061600 ;
    PORT
      LAYER Metal3 ;
        RECT 238.640 35.500 239.040 35.900 ;
    END
  END WW4END[1]
  PIN WW4END[2]
    DIRECTION INPUT ;
    USE SIGNAL ;
    ANTENNAGATEAREA 0.878800 ;
    PORT
      LAYER Metal3 ;
        RECT 238.640 37.180 239.040 37.580 ;
    END
  END WW4END[2]
  PIN WW4END[3]
    DIRECTION INPUT ;
    USE SIGNAL ;
    ANTENNAGATEAREA 0.833300 ;
    PORT
      LAYER Metal3 ;
        RECT 238.640 38.860 239.040 39.260 ;
    END
  END WW4END[3]
  PIN WW4END[4]
    DIRECTION INPUT ;
    USE SIGNAL ;
    ANTENNAGATEAREA 0.789100 ;
    ANTENNADIFFAREA 2.015400 ;
    PORT
      LAYER Metal3 ;
        RECT 238.640 40.540 239.040 40.940 ;
    END
  END WW4END[4]
  PIN WW4END[5]
    DIRECTION INPUT ;
    USE SIGNAL ;
    ANTENNAGATEAREA 0.180700 ;
    PORT
      LAYER Metal3 ;
        RECT 238.640 42.220 239.040 42.620 ;
    END
  END WW4END[5]
  PIN WW4END[6]
    DIRECTION INPUT ;
    USE SIGNAL ;
    ANTENNAGATEAREA 0.789100 ;
    ANTENNADIFFAREA 2.015400 ;
    PORT
      LAYER Metal3 ;
        RECT 238.640 43.900 239.040 44.300 ;
    END
  END WW4END[6]
  PIN WW4END[7]
    DIRECTION INPUT ;
    USE SIGNAL ;
    ANTENNAGATEAREA 0.789100 ;
    ANTENNADIFFAREA 2.015400 ;
    PORT
      LAYER Metal3 ;
        RECT 238.640 45.580 239.040 45.980 ;
    END
  END WW4END[7]
  PIN WW4END[8]
    DIRECTION INPUT ;
    USE SIGNAL ;
    ANTENNAGATEAREA 0.789100 ;
    ANTENNADIFFAREA 2.015400 ;
    PORT
      LAYER Metal3 ;
        RECT 238.640 47.260 239.040 47.660 ;
    END
  END WW4END[8]
  PIN WW4END[9]
    DIRECTION INPUT ;
    USE SIGNAL ;
    ANTENNAGATEAREA 0.789100 ;
    ANTENNADIFFAREA 2.015400 ;
    PORT
      LAYER Metal3 ;
        RECT 238.640 48.940 239.040 49.340 ;
    END
  END WW4END[9]
  OBS
      LAYER GatPoly ;
        RECT 2.880 3.630 236.160 211.830 ;
      LAYER Metal1 ;
        RECT 2.880 3.560 236.160 211.900 ;
      LAYER Metal2 ;
        RECT 0.375 214.850 59.590 215.185 ;
        RECT 60.410 214.850 60.550 215.185 ;
        RECT 61.370 214.850 61.510 215.185 ;
        RECT 62.330 214.850 62.470 215.185 ;
        RECT 63.290 214.850 63.430 215.185 ;
        RECT 64.250 214.850 64.390 215.185 ;
        RECT 65.210 214.850 65.350 215.185 ;
        RECT 66.170 214.850 66.310 215.185 ;
        RECT 67.130 214.850 67.270 215.185 ;
        RECT 68.090 214.850 68.230 215.185 ;
        RECT 69.050 214.850 69.190 215.185 ;
        RECT 70.010 214.850 70.150 215.185 ;
        RECT 70.970 214.850 71.110 215.185 ;
        RECT 71.930 214.850 72.070 215.185 ;
        RECT 72.890 214.850 73.030 215.185 ;
        RECT 73.850 214.850 73.990 215.185 ;
        RECT 74.810 214.850 74.950 215.185 ;
        RECT 75.770 214.850 75.910 215.185 ;
        RECT 76.730 214.850 76.870 215.185 ;
        RECT 77.690 214.850 77.830 215.185 ;
        RECT 78.650 214.850 78.790 215.185 ;
        RECT 79.610 214.850 79.750 215.185 ;
        RECT 80.570 214.850 80.710 215.185 ;
        RECT 81.530 214.850 81.670 215.185 ;
        RECT 82.490 214.850 82.630 215.185 ;
        RECT 83.450 214.850 83.590 215.185 ;
        RECT 84.410 214.850 84.550 215.185 ;
        RECT 85.370 214.850 85.510 215.185 ;
        RECT 86.330 214.850 86.470 215.185 ;
        RECT 87.290 214.850 87.430 215.185 ;
        RECT 88.250 214.850 88.390 215.185 ;
        RECT 89.210 214.850 89.350 215.185 ;
        RECT 90.170 214.850 90.310 215.185 ;
        RECT 91.130 214.850 91.270 215.185 ;
        RECT 92.090 214.850 92.230 215.185 ;
        RECT 93.050 214.850 93.190 215.185 ;
        RECT 94.010 214.850 94.150 215.185 ;
        RECT 94.970 214.850 95.110 215.185 ;
        RECT 95.930 214.850 96.070 215.185 ;
        RECT 96.890 214.850 97.030 215.185 ;
        RECT 97.850 214.850 97.990 215.185 ;
        RECT 98.810 214.850 98.950 215.185 ;
        RECT 99.770 214.850 99.910 215.185 ;
        RECT 100.730 214.850 100.870 215.185 ;
        RECT 101.690 214.850 101.830 215.185 ;
        RECT 102.650 214.850 102.790 215.185 ;
        RECT 103.610 214.850 103.750 215.185 ;
        RECT 104.570 214.850 104.710 215.185 ;
        RECT 105.530 214.850 105.670 215.185 ;
        RECT 106.490 214.850 106.630 215.185 ;
        RECT 107.450 214.850 107.590 215.185 ;
        RECT 108.410 214.850 108.550 215.185 ;
        RECT 109.370 214.850 109.510 215.185 ;
        RECT 110.330 214.850 110.470 215.185 ;
        RECT 111.290 214.850 111.430 215.185 ;
        RECT 112.250 214.850 112.390 215.185 ;
        RECT 113.210 214.850 113.350 215.185 ;
        RECT 114.170 214.850 114.310 215.185 ;
        RECT 115.130 214.850 115.270 215.185 ;
        RECT 116.090 214.850 116.230 215.185 ;
        RECT 117.050 214.850 117.190 215.185 ;
        RECT 118.010 214.850 118.150 215.185 ;
        RECT 118.970 214.850 119.110 215.185 ;
        RECT 119.930 214.850 120.070 215.185 ;
        RECT 120.890 214.850 121.030 215.185 ;
        RECT 121.850 214.850 121.990 215.185 ;
        RECT 122.810 214.850 122.950 215.185 ;
        RECT 123.770 214.850 123.910 215.185 ;
        RECT 124.730 214.850 124.870 215.185 ;
        RECT 125.690 214.850 125.830 215.185 ;
        RECT 126.650 214.850 126.790 215.185 ;
        RECT 127.610 214.850 127.750 215.185 ;
        RECT 128.570 214.850 128.710 215.185 ;
        RECT 129.530 214.850 129.670 215.185 ;
        RECT 130.490 214.850 130.630 215.185 ;
        RECT 131.450 214.850 131.590 215.185 ;
        RECT 132.410 214.850 132.550 215.185 ;
        RECT 133.370 214.850 133.510 215.185 ;
        RECT 134.330 214.850 134.470 215.185 ;
        RECT 135.290 214.850 135.430 215.185 ;
        RECT 136.250 214.850 136.390 215.185 ;
        RECT 137.210 214.850 137.350 215.185 ;
        RECT 138.170 214.850 138.310 215.185 ;
        RECT 139.130 214.850 139.270 215.185 ;
        RECT 140.090 214.850 140.230 215.185 ;
        RECT 141.050 214.850 141.190 215.185 ;
        RECT 142.010 214.850 142.150 215.185 ;
        RECT 142.970 214.850 143.110 215.185 ;
        RECT 143.930 214.850 144.070 215.185 ;
        RECT 144.890 214.850 145.030 215.185 ;
        RECT 145.850 214.850 145.990 215.185 ;
        RECT 146.810 214.850 146.950 215.185 ;
        RECT 147.770 214.850 147.910 215.185 ;
        RECT 148.730 214.850 148.870 215.185 ;
        RECT 149.690 214.850 149.830 215.185 ;
        RECT 150.650 214.850 150.790 215.185 ;
        RECT 151.610 214.850 151.750 215.185 ;
        RECT 152.570 214.850 152.710 215.185 ;
        RECT 153.530 214.850 153.670 215.185 ;
        RECT 154.490 214.850 154.630 215.185 ;
        RECT 155.450 214.850 155.590 215.185 ;
        RECT 156.410 214.850 156.550 215.185 ;
        RECT 157.370 214.850 157.510 215.185 ;
        RECT 158.330 214.850 158.470 215.185 ;
        RECT 159.290 214.850 159.430 215.185 ;
        RECT 160.250 214.850 160.390 215.185 ;
        RECT 161.210 214.850 161.350 215.185 ;
        RECT 162.170 214.850 162.310 215.185 ;
        RECT 163.130 214.850 163.270 215.185 ;
        RECT 164.090 214.850 164.230 215.185 ;
        RECT 165.050 214.850 165.190 215.185 ;
        RECT 166.010 214.850 166.150 215.185 ;
        RECT 166.970 214.850 167.110 215.185 ;
        RECT 167.930 214.850 168.070 215.185 ;
        RECT 168.890 214.850 169.030 215.185 ;
        RECT 169.850 214.850 169.990 215.185 ;
        RECT 170.810 214.850 170.950 215.185 ;
        RECT 171.770 214.850 171.910 215.185 ;
        RECT 172.730 214.850 172.870 215.185 ;
        RECT 173.690 214.850 173.830 215.185 ;
        RECT 174.650 214.850 174.790 215.185 ;
        RECT 175.610 214.850 175.750 215.185 ;
        RECT 176.570 214.850 176.710 215.185 ;
        RECT 177.530 214.850 177.670 215.185 ;
        RECT 178.490 214.850 178.630 215.185 ;
        RECT 179.450 214.850 238.665 215.185 ;
        RECT 0.375 0.610 238.665 214.850 ;
        RECT 0.375 0.275 59.590 0.610 ;
        RECT 60.410 0.275 60.550 0.610 ;
        RECT 61.370 0.275 61.510 0.610 ;
        RECT 62.330 0.275 62.470 0.610 ;
        RECT 63.290 0.275 63.430 0.610 ;
        RECT 64.250 0.275 64.390 0.610 ;
        RECT 65.210 0.275 65.350 0.610 ;
        RECT 66.170 0.275 66.310 0.610 ;
        RECT 67.130 0.275 67.270 0.610 ;
        RECT 68.090 0.275 68.230 0.610 ;
        RECT 69.050 0.275 69.190 0.610 ;
        RECT 70.010 0.275 70.150 0.610 ;
        RECT 70.970 0.275 71.110 0.610 ;
        RECT 71.930 0.275 72.070 0.610 ;
        RECT 72.890 0.275 73.030 0.610 ;
        RECT 73.850 0.275 73.990 0.610 ;
        RECT 74.810 0.275 74.950 0.610 ;
        RECT 75.770 0.275 75.910 0.610 ;
        RECT 76.730 0.275 76.870 0.610 ;
        RECT 77.690 0.275 77.830 0.610 ;
        RECT 78.650 0.275 78.790 0.610 ;
        RECT 79.610 0.275 79.750 0.610 ;
        RECT 80.570 0.275 80.710 0.610 ;
        RECT 81.530 0.275 81.670 0.610 ;
        RECT 82.490 0.275 82.630 0.610 ;
        RECT 83.450 0.275 83.590 0.610 ;
        RECT 84.410 0.275 84.550 0.610 ;
        RECT 85.370 0.275 85.510 0.610 ;
        RECT 86.330 0.275 86.470 0.610 ;
        RECT 87.290 0.275 87.430 0.610 ;
        RECT 88.250 0.275 88.390 0.610 ;
        RECT 89.210 0.275 89.350 0.610 ;
        RECT 90.170 0.275 90.310 0.610 ;
        RECT 91.130 0.275 91.270 0.610 ;
        RECT 92.090 0.275 92.230 0.610 ;
        RECT 93.050 0.275 93.190 0.610 ;
        RECT 94.010 0.275 94.150 0.610 ;
        RECT 94.970 0.275 95.110 0.610 ;
        RECT 95.930 0.275 96.070 0.610 ;
        RECT 96.890 0.275 97.030 0.610 ;
        RECT 97.850 0.275 97.990 0.610 ;
        RECT 98.810 0.275 98.950 0.610 ;
        RECT 99.770 0.275 99.910 0.610 ;
        RECT 100.730 0.275 100.870 0.610 ;
        RECT 101.690 0.275 101.830 0.610 ;
        RECT 102.650 0.275 102.790 0.610 ;
        RECT 103.610 0.275 103.750 0.610 ;
        RECT 104.570 0.275 104.710 0.610 ;
        RECT 105.530 0.275 105.670 0.610 ;
        RECT 106.490 0.275 106.630 0.610 ;
        RECT 107.450 0.275 107.590 0.610 ;
        RECT 108.410 0.275 108.550 0.610 ;
        RECT 109.370 0.275 109.510 0.610 ;
        RECT 110.330 0.275 110.470 0.610 ;
        RECT 111.290 0.275 111.430 0.610 ;
        RECT 112.250 0.275 112.390 0.610 ;
        RECT 113.210 0.275 113.350 0.610 ;
        RECT 114.170 0.275 114.310 0.610 ;
        RECT 115.130 0.275 115.270 0.610 ;
        RECT 116.090 0.275 116.230 0.610 ;
        RECT 117.050 0.275 117.190 0.610 ;
        RECT 118.010 0.275 118.150 0.610 ;
        RECT 118.970 0.275 119.110 0.610 ;
        RECT 119.930 0.275 120.070 0.610 ;
        RECT 120.890 0.275 121.030 0.610 ;
        RECT 121.850 0.275 121.990 0.610 ;
        RECT 122.810 0.275 122.950 0.610 ;
        RECT 123.770 0.275 123.910 0.610 ;
        RECT 124.730 0.275 124.870 0.610 ;
        RECT 125.690 0.275 125.830 0.610 ;
        RECT 126.650 0.275 126.790 0.610 ;
        RECT 127.610 0.275 127.750 0.610 ;
        RECT 128.570 0.275 128.710 0.610 ;
        RECT 129.530 0.275 129.670 0.610 ;
        RECT 130.490 0.275 130.630 0.610 ;
        RECT 131.450 0.275 131.590 0.610 ;
        RECT 132.410 0.275 132.550 0.610 ;
        RECT 133.370 0.275 133.510 0.610 ;
        RECT 134.330 0.275 134.470 0.610 ;
        RECT 135.290 0.275 135.430 0.610 ;
        RECT 136.250 0.275 136.390 0.610 ;
        RECT 137.210 0.275 137.350 0.610 ;
        RECT 138.170 0.275 138.310 0.610 ;
        RECT 139.130 0.275 139.270 0.610 ;
        RECT 140.090 0.275 140.230 0.610 ;
        RECT 141.050 0.275 141.190 0.610 ;
        RECT 142.010 0.275 142.150 0.610 ;
        RECT 142.970 0.275 143.110 0.610 ;
        RECT 143.930 0.275 144.070 0.610 ;
        RECT 144.890 0.275 145.030 0.610 ;
        RECT 145.850 0.275 145.990 0.610 ;
        RECT 146.810 0.275 146.950 0.610 ;
        RECT 147.770 0.275 147.910 0.610 ;
        RECT 148.730 0.275 148.870 0.610 ;
        RECT 149.690 0.275 149.830 0.610 ;
        RECT 150.650 0.275 150.790 0.610 ;
        RECT 151.610 0.275 151.750 0.610 ;
        RECT 152.570 0.275 152.710 0.610 ;
        RECT 153.530 0.275 153.670 0.610 ;
        RECT 154.490 0.275 154.630 0.610 ;
        RECT 155.450 0.275 155.590 0.610 ;
        RECT 156.410 0.275 156.550 0.610 ;
        RECT 157.370 0.275 157.510 0.610 ;
        RECT 158.330 0.275 158.470 0.610 ;
        RECT 159.290 0.275 159.430 0.610 ;
        RECT 160.250 0.275 160.390 0.610 ;
        RECT 161.210 0.275 161.350 0.610 ;
        RECT 162.170 0.275 162.310 0.610 ;
        RECT 163.130 0.275 163.270 0.610 ;
        RECT 164.090 0.275 164.230 0.610 ;
        RECT 165.050 0.275 165.190 0.610 ;
        RECT 166.010 0.275 166.150 0.610 ;
        RECT 166.970 0.275 167.110 0.610 ;
        RECT 167.930 0.275 168.070 0.610 ;
        RECT 168.890 0.275 169.030 0.610 ;
        RECT 169.850 0.275 169.990 0.610 ;
        RECT 170.810 0.275 170.950 0.610 ;
        RECT 171.770 0.275 171.910 0.610 ;
        RECT 172.730 0.275 172.870 0.610 ;
        RECT 173.690 0.275 173.830 0.610 ;
        RECT 174.650 0.275 174.790 0.610 ;
        RECT 175.610 0.275 175.750 0.610 ;
        RECT 176.570 0.275 176.710 0.610 ;
        RECT 177.530 0.275 177.670 0.610 ;
        RECT 178.490 0.275 178.630 0.610 ;
        RECT 179.450 0.275 238.665 0.610 ;
      LAYER Metal3 ;
        RECT 0.335 214.190 238.705 215.145 ;
        RECT 0.610 213.370 238.430 214.190 ;
        RECT 0.335 212.510 238.705 213.370 ;
        RECT 0.610 211.690 238.430 212.510 ;
        RECT 0.335 210.830 238.705 211.690 ;
        RECT 0.610 210.010 238.430 210.830 ;
        RECT 0.335 209.150 238.705 210.010 ;
        RECT 0.610 208.330 238.430 209.150 ;
        RECT 0.335 207.470 238.705 208.330 ;
        RECT 0.610 206.650 238.430 207.470 ;
        RECT 0.335 205.790 238.705 206.650 ;
        RECT 0.610 204.970 238.430 205.790 ;
        RECT 0.335 204.110 238.705 204.970 ;
        RECT 0.610 203.290 238.430 204.110 ;
        RECT 0.335 202.430 238.705 203.290 ;
        RECT 0.610 201.610 238.430 202.430 ;
        RECT 0.335 200.750 238.705 201.610 ;
        RECT 0.610 199.930 238.430 200.750 ;
        RECT 0.335 199.070 238.705 199.930 ;
        RECT 0.610 198.250 238.430 199.070 ;
        RECT 0.335 197.390 238.705 198.250 ;
        RECT 0.610 196.570 238.430 197.390 ;
        RECT 0.335 195.710 238.705 196.570 ;
        RECT 0.610 194.890 238.430 195.710 ;
        RECT 0.335 194.030 238.705 194.890 ;
        RECT 0.610 193.210 238.430 194.030 ;
        RECT 0.335 192.350 238.705 193.210 ;
        RECT 0.610 191.530 238.430 192.350 ;
        RECT 0.335 190.670 238.705 191.530 ;
        RECT 0.610 189.850 238.430 190.670 ;
        RECT 0.335 188.990 238.705 189.850 ;
        RECT 0.610 188.170 238.430 188.990 ;
        RECT 0.335 187.310 238.705 188.170 ;
        RECT 0.610 186.490 238.430 187.310 ;
        RECT 0.335 185.630 238.705 186.490 ;
        RECT 0.610 184.810 238.430 185.630 ;
        RECT 0.335 183.950 238.705 184.810 ;
        RECT 0.610 183.130 238.430 183.950 ;
        RECT 0.335 182.270 238.705 183.130 ;
        RECT 0.610 181.450 238.430 182.270 ;
        RECT 0.335 180.590 238.705 181.450 ;
        RECT 0.610 179.770 238.430 180.590 ;
        RECT 0.335 178.910 238.705 179.770 ;
        RECT 0.610 178.090 238.430 178.910 ;
        RECT 0.335 177.230 238.705 178.090 ;
        RECT 0.610 176.410 238.430 177.230 ;
        RECT 0.335 175.550 238.705 176.410 ;
        RECT 0.610 174.730 238.430 175.550 ;
        RECT 0.335 173.870 238.705 174.730 ;
        RECT 0.610 173.050 238.430 173.870 ;
        RECT 0.335 172.190 238.705 173.050 ;
        RECT 0.610 171.370 238.430 172.190 ;
        RECT 0.335 170.510 238.705 171.370 ;
        RECT 0.610 169.690 238.430 170.510 ;
        RECT 0.335 168.830 238.705 169.690 ;
        RECT 0.610 168.010 238.430 168.830 ;
        RECT 0.335 167.150 238.705 168.010 ;
        RECT 0.610 166.330 238.430 167.150 ;
        RECT 0.335 165.470 238.705 166.330 ;
        RECT 0.610 164.650 238.430 165.470 ;
        RECT 0.335 163.790 238.705 164.650 ;
        RECT 0.610 162.970 238.430 163.790 ;
        RECT 0.335 162.110 238.705 162.970 ;
        RECT 0.610 161.290 238.430 162.110 ;
        RECT 0.335 160.430 238.705 161.290 ;
        RECT 0.610 159.610 238.430 160.430 ;
        RECT 0.335 158.750 238.705 159.610 ;
        RECT 0.610 157.930 238.430 158.750 ;
        RECT 0.335 157.070 238.705 157.930 ;
        RECT 0.610 156.250 238.430 157.070 ;
        RECT 0.335 155.390 238.705 156.250 ;
        RECT 0.610 154.570 238.430 155.390 ;
        RECT 0.335 153.710 238.705 154.570 ;
        RECT 0.610 152.890 238.430 153.710 ;
        RECT 0.335 152.030 238.705 152.890 ;
        RECT 0.610 151.210 238.430 152.030 ;
        RECT 0.335 150.350 238.705 151.210 ;
        RECT 0.610 149.530 238.430 150.350 ;
        RECT 0.335 148.670 238.705 149.530 ;
        RECT 0.610 147.850 238.430 148.670 ;
        RECT 0.335 146.990 238.705 147.850 ;
        RECT 0.610 146.170 238.430 146.990 ;
        RECT 0.335 145.310 238.705 146.170 ;
        RECT 0.610 144.490 238.430 145.310 ;
        RECT 0.335 143.630 238.705 144.490 ;
        RECT 0.610 142.810 238.430 143.630 ;
        RECT 0.335 141.950 238.705 142.810 ;
        RECT 0.610 141.130 238.430 141.950 ;
        RECT 0.335 140.270 238.705 141.130 ;
        RECT 0.610 139.450 238.430 140.270 ;
        RECT 0.335 138.590 238.705 139.450 ;
        RECT 0.610 137.770 238.430 138.590 ;
        RECT 0.335 136.910 238.705 137.770 ;
        RECT 0.610 136.090 238.430 136.910 ;
        RECT 0.335 135.230 238.705 136.090 ;
        RECT 0.610 134.410 238.430 135.230 ;
        RECT 0.335 133.550 238.705 134.410 ;
        RECT 0.610 132.730 238.430 133.550 ;
        RECT 0.335 131.870 238.705 132.730 ;
        RECT 0.610 131.050 238.430 131.870 ;
        RECT 0.335 130.190 238.705 131.050 ;
        RECT 0.610 129.370 238.430 130.190 ;
        RECT 0.335 128.510 238.705 129.370 ;
        RECT 0.610 127.690 238.430 128.510 ;
        RECT 0.335 126.830 238.705 127.690 ;
        RECT 0.610 126.010 238.430 126.830 ;
        RECT 0.335 125.150 238.705 126.010 ;
        RECT 0.610 124.330 238.430 125.150 ;
        RECT 0.335 123.470 238.705 124.330 ;
        RECT 0.610 122.650 238.430 123.470 ;
        RECT 0.335 121.790 238.705 122.650 ;
        RECT 0.610 120.970 238.430 121.790 ;
        RECT 0.335 120.110 238.705 120.970 ;
        RECT 0.610 119.290 238.430 120.110 ;
        RECT 0.335 118.430 238.705 119.290 ;
        RECT 0.610 117.610 238.430 118.430 ;
        RECT 0.335 116.750 238.705 117.610 ;
        RECT 0.610 115.930 238.430 116.750 ;
        RECT 0.335 115.070 238.705 115.930 ;
        RECT 0.610 114.250 238.430 115.070 ;
        RECT 0.335 113.390 238.705 114.250 ;
        RECT 0.610 112.570 238.430 113.390 ;
        RECT 0.335 111.710 238.705 112.570 ;
        RECT 0.610 110.890 238.430 111.710 ;
        RECT 0.335 110.030 238.705 110.890 ;
        RECT 0.610 109.210 238.430 110.030 ;
        RECT 0.335 108.350 238.705 109.210 ;
        RECT 0.610 107.530 238.430 108.350 ;
        RECT 0.335 106.670 238.705 107.530 ;
        RECT 0.610 105.850 238.430 106.670 ;
        RECT 0.335 104.990 238.705 105.850 ;
        RECT 0.610 104.170 238.430 104.990 ;
        RECT 0.335 103.310 238.705 104.170 ;
        RECT 0.610 102.490 238.430 103.310 ;
        RECT 0.335 101.630 238.705 102.490 ;
        RECT 0.610 100.810 238.430 101.630 ;
        RECT 0.335 99.950 238.705 100.810 ;
        RECT 0.610 99.130 238.430 99.950 ;
        RECT 0.335 98.270 238.705 99.130 ;
        RECT 0.610 97.450 238.430 98.270 ;
        RECT 0.335 96.590 238.705 97.450 ;
        RECT 0.610 95.770 238.430 96.590 ;
        RECT 0.335 94.910 238.705 95.770 ;
        RECT 0.610 94.090 238.430 94.910 ;
        RECT 0.335 93.230 238.705 94.090 ;
        RECT 0.610 92.410 238.430 93.230 ;
        RECT 0.335 91.550 238.705 92.410 ;
        RECT 0.610 90.730 238.430 91.550 ;
        RECT 0.335 89.870 238.705 90.730 ;
        RECT 0.610 89.050 238.430 89.870 ;
        RECT 0.335 88.190 238.705 89.050 ;
        RECT 0.610 87.370 238.430 88.190 ;
        RECT 0.335 86.510 238.705 87.370 ;
        RECT 0.610 85.690 238.430 86.510 ;
        RECT 0.335 84.830 238.705 85.690 ;
        RECT 0.610 84.010 238.430 84.830 ;
        RECT 0.335 83.150 238.705 84.010 ;
        RECT 0.610 82.330 238.430 83.150 ;
        RECT 0.335 81.470 238.705 82.330 ;
        RECT 0.610 80.650 238.430 81.470 ;
        RECT 0.335 79.790 238.705 80.650 ;
        RECT 0.610 78.970 238.430 79.790 ;
        RECT 0.335 78.110 238.705 78.970 ;
        RECT 0.610 77.290 238.430 78.110 ;
        RECT 0.335 76.430 238.705 77.290 ;
        RECT 0.610 75.610 238.430 76.430 ;
        RECT 0.335 74.750 238.705 75.610 ;
        RECT 0.610 73.930 238.430 74.750 ;
        RECT 0.335 73.070 238.705 73.930 ;
        RECT 0.610 72.250 238.430 73.070 ;
        RECT 0.335 71.390 238.705 72.250 ;
        RECT 0.610 70.570 238.430 71.390 ;
        RECT 0.335 69.710 238.705 70.570 ;
        RECT 0.610 68.890 238.430 69.710 ;
        RECT 0.335 68.030 238.705 68.890 ;
        RECT 0.610 67.210 238.430 68.030 ;
        RECT 0.335 66.350 238.705 67.210 ;
        RECT 0.610 65.530 238.430 66.350 ;
        RECT 0.335 64.670 238.705 65.530 ;
        RECT 0.610 63.850 238.430 64.670 ;
        RECT 0.335 62.990 238.705 63.850 ;
        RECT 0.610 62.170 238.430 62.990 ;
        RECT 0.335 61.310 238.705 62.170 ;
        RECT 0.610 60.490 238.430 61.310 ;
        RECT 0.335 59.630 238.705 60.490 ;
        RECT 0.610 58.810 238.430 59.630 ;
        RECT 0.335 57.950 238.705 58.810 ;
        RECT 0.610 57.130 238.430 57.950 ;
        RECT 0.335 56.270 238.705 57.130 ;
        RECT 0.610 55.450 238.430 56.270 ;
        RECT 0.335 54.590 238.705 55.450 ;
        RECT 0.610 53.770 238.430 54.590 ;
        RECT 0.335 52.910 238.705 53.770 ;
        RECT 0.610 52.090 238.430 52.910 ;
        RECT 0.335 51.230 238.705 52.090 ;
        RECT 0.610 50.410 238.430 51.230 ;
        RECT 0.335 49.550 238.705 50.410 ;
        RECT 0.610 48.730 238.430 49.550 ;
        RECT 0.335 47.870 238.705 48.730 ;
        RECT 0.610 47.050 238.430 47.870 ;
        RECT 0.335 46.190 238.705 47.050 ;
        RECT 0.610 45.370 238.430 46.190 ;
        RECT 0.335 44.510 238.705 45.370 ;
        RECT 0.610 43.690 238.430 44.510 ;
        RECT 0.335 42.830 238.705 43.690 ;
        RECT 0.610 42.010 238.430 42.830 ;
        RECT 0.335 41.150 238.705 42.010 ;
        RECT 0.610 40.330 238.430 41.150 ;
        RECT 0.335 39.470 238.705 40.330 ;
        RECT 0.610 38.650 238.430 39.470 ;
        RECT 0.335 37.790 238.705 38.650 ;
        RECT 0.610 36.970 238.430 37.790 ;
        RECT 0.335 36.110 238.705 36.970 ;
        RECT 0.610 35.290 238.430 36.110 ;
        RECT 0.335 34.430 238.705 35.290 ;
        RECT 0.610 33.610 238.430 34.430 ;
        RECT 0.335 32.750 238.705 33.610 ;
        RECT 0.610 31.930 238.430 32.750 ;
        RECT 0.335 31.070 238.705 31.930 ;
        RECT 0.610 30.250 238.430 31.070 ;
        RECT 0.335 29.390 238.705 30.250 ;
        RECT 0.610 28.570 238.430 29.390 ;
        RECT 0.335 27.710 238.705 28.570 ;
        RECT 0.610 26.890 238.430 27.710 ;
        RECT 0.335 26.030 238.705 26.890 ;
        RECT 0.610 25.210 238.430 26.030 ;
        RECT 0.335 24.350 238.705 25.210 ;
        RECT 0.610 23.530 238.430 24.350 ;
        RECT 0.335 22.670 238.705 23.530 ;
        RECT 0.610 21.850 238.430 22.670 ;
        RECT 0.335 20.990 238.705 21.850 ;
        RECT 0.610 20.170 238.430 20.990 ;
        RECT 0.335 19.310 238.705 20.170 ;
        RECT 0.610 18.490 238.430 19.310 ;
        RECT 0.335 17.630 238.705 18.490 ;
        RECT 0.610 16.810 238.430 17.630 ;
        RECT 0.335 15.950 238.705 16.810 ;
        RECT 0.610 15.130 238.430 15.950 ;
        RECT 0.335 14.270 238.705 15.130 ;
        RECT 0.610 13.450 238.430 14.270 ;
        RECT 0.335 12.590 238.705 13.450 ;
        RECT 0.610 11.770 238.430 12.590 ;
        RECT 0.335 10.910 238.705 11.770 ;
        RECT 0.610 10.090 238.430 10.910 ;
        RECT 0.335 9.230 238.705 10.090 ;
        RECT 0.610 8.410 238.430 9.230 ;
        RECT 0.335 7.550 238.705 8.410 ;
        RECT 0.610 6.730 238.430 7.550 ;
        RECT 0.335 5.870 238.705 6.730 ;
        RECT 0.610 5.050 238.430 5.870 ;
        RECT 0.335 4.190 238.705 5.050 ;
        RECT 0.610 3.370 238.430 4.190 ;
        RECT 0.335 2.510 238.705 3.370 ;
        RECT 0.610 1.690 238.430 2.510 ;
        RECT 0.335 0.830 238.705 1.690 ;
        RECT 0.610 0.315 238.430 0.830 ;
      LAYER Metal4 ;
        RECT 0.375 0.270 238.660 215.185 ;
      LAYER Metal5 ;
        RECT 0.335 0.320 238.225 215.140 ;
      LAYER TopMetal1 ;
        RECT 5.380 2.960 13.740 208.720 ;
        RECT 19.220 2.960 19.940 208.720 ;
        RECT 25.420 2.960 89.340 208.720 ;
        RECT 94.820 2.960 95.540 208.720 ;
        RECT 101.020 2.960 164.940 208.720 ;
        RECT 170.420 2.960 171.140 208.720 ;
        RECT 176.620 2.960 225.900 208.720 ;
  END
END RegFile
END LIBRARY

